VERSION 5.7 ;
  NOWIREEXTENSIONATPIN ON ;
  DIVIDERCHAR "/" ;
  BUSBITCHARS "[]" ;
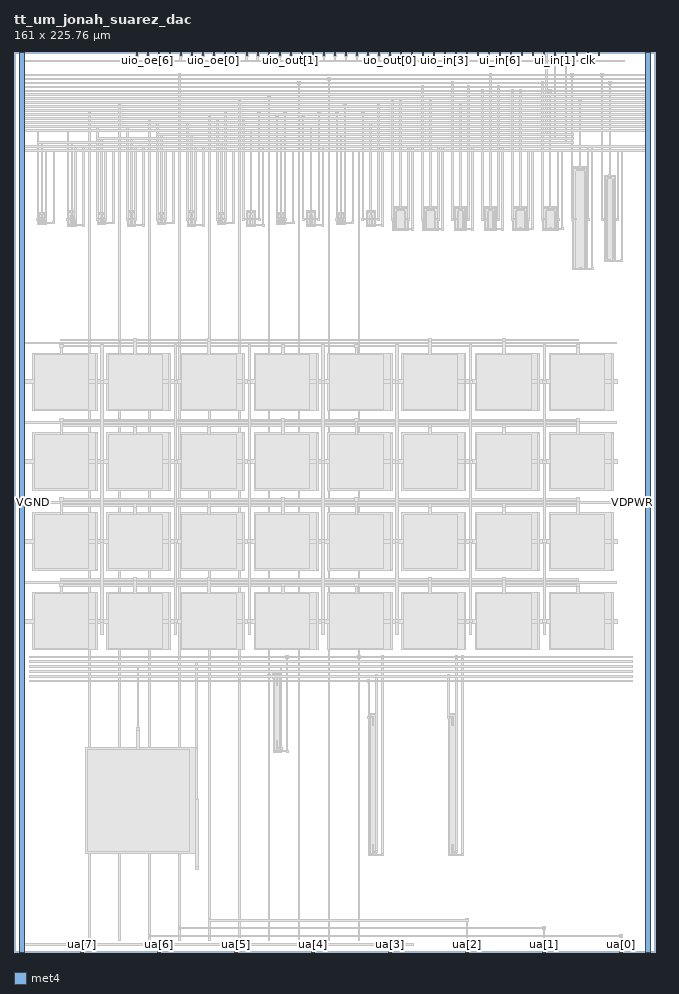
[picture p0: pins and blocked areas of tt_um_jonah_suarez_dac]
MACRO tt_um_jonah_suarez_dac
  CLASS BLOCK ;
  FOREIGN tt_um_jonah_suarez_dac ;
  ORIGIN 0.000 0.000 ;
  SIZE 161.000 BY 225.760 ;
  PIN clk
    DIRECTION INPUT ;
    USE SIGNAL ;
    PORT
      LAYER met4 ;
        RECT 143.830 224.760 144.130 225.760 ;
    END
  END clk
  PIN ena
    DIRECTION INPUT ;
    USE SIGNAL ;
    PORT
      LAYER met4 ;
        RECT 146.590 224.760 146.890 225.760 ;
    END
  END ena
  PIN rst_n
    DIRECTION INPUT ;
    USE SIGNAL ;
    PORT
      LAYER met4 ;
        RECT 141.070 224.760 141.370 225.760 ;
    END
  END rst_n
  PIN ua[0]
    DIRECTION INOUT ;
    USE SIGNAL ;
    ANTENNADIFFAREA 0.870000 ;
    PORT
      LAYER met4 ;
        RECT 151.810 0.000 152.710 1.000 ;
    END
  END ua[0]
  PIN ua[1]
    DIRECTION INOUT ;
    USE SIGNAL ;
    ANTENNAGATEAREA 4.000000 ;
    ANTENNADIFFAREA 12.759999 ;
    PORT
      LAYER met4 ;
        RECT 132.490 0.000 133.390 1.000 ;
    END
  END ua[1]
  PIN ua[2]
    DIRECTION INOUT ;
    USE SIGNAL ;
    ANTENNADIFFAREA 0.870000 ;
    PORT
      LAYER met4 ;
        RECT 113.170 0.000 114.070 1.000 ;
    END
  END ua[2]
  PIN ua[3]
    DIRECTION INOUT ;
    USE SIGNAL ;
    PORT
      LAYER met4 ;
        RECT 93.850 0.000 94.750 1.000 ;
    END
  END ua[3]
  PIN ua[4]
    DIRECTION INOUT ;
    USE SIGNAL ;
    PORT
      LAYER met4 ;
        RECT 74.530 0.000 75.430 1.000 ;
    END
  END ua[4]
  PIN ua[5]
    DIRECTION INOUT ;
    USE SIGNAL ;
    PORT
      LAYER met4 ;
        RECT 55.210 0.000 56.110 1.000 ;
    END
  END ua[5]
  PIN ua[6]
    DIRECTION INOUT ;
    USE SIGNAL ;
    PORT
      LAYER met4 ;
        RECT 35.890 0.000 36.790 1.000 ;
    END
  END ua[6]
  PIN ua[7]
    DIRECTION INOUT ;
    USE SIGNAL ;
    PORT
      LAYER met4 ;
        RECT 16.570 0.000 17.470 1.000 ;
    END
  END ua[7]
  PIN ui_in[0]
    DIRECTION INPUT ;
    USE SIGNAL ;
    ANTENNAGATEAREA 0.600000 ;
    PORT
      LAYER met4 ;
        RECT 138.310 224.760 138.610 225.760 ;
    END
  END ui_in[0]
  PIN ui_in[1]
    DIRECTION INPUT ;
    USE SIGNAL ;
    ANTENNAGATEAREA 0.600000 ;
    PORT
      LAYER met4 ;
        RECT 135.550 224.760 135.850 225.760 ;
    END
  END ui_in[1]
  PIN ui_in[2]
    DIRECTION INPUT ;
    USE SIGNAL ;
    ANTENNAGATEAREA 0.600000 ;
    PORT
      LAYER met4 ;
        RECT 132.790 224.760 133.090 225.760 ;
    END
  END ui_in[2]
  PIN ui_in[3]
    DIRECTION INPUT ;
    USE SIGNAL ;
    PORT
      LAYER met4 ;
        RECT 130.030 224.760 130.330 225.760 ;
    END
  END ui_in[3]
  PIN ui_in[4]
    DIRECTION INPUT ;
    USE SIGNAL ;
    PORT
      LAYER met4 ;
        RECT 127.270 224.760 127.570 225.760 ;
    END
  END ui_in[4]
  PIN ui_in[5]
    DIRECTION INPUT ;
    USE SIGNAL ;
    PORT
      LAYER met4 ;
        RECT 124.510 224.760 124.810 225.760 ;
    END
  END ui_in[5]
  PIN ui_in[6]
    DIRECTION INPUT ;
    USE SIGNAL ;
    PORT
      LAYER met4 ;
        RECT 121.750 224.760 122.050 225.760 ;
    END
  END ui_in[6]
  PIN ui_in[7]
    DIRECTION INPUT ;
    USE SIGNAL ;
    PORT
      LAYER met4 ;
        RECT 118.990 224.760 119.290 225.760 ;
    END
  END ui_in[7]
  PIN uio_in[0]
    DIRECTION INPUT ;
    USE SIGNAL ;
    PORT
      LAYER met4 ;
        RECT 116.230 224.760 116.530 225.760 ;
    END
  END uio_in[0]
  PIN uio_in[1]
    DIRECTION INPUT ;
    USE SIGNAL ;
    PORT
      LAYER met4 ;
        RECT 113.470 224.760 113.770 225.760 ;
    END
  END uio_in[1]
  PIN uio_in[2]
    DIRECTION INPUT ;
    USE SIGNAL ;
    PORT
      LAYER met4 ;
        RECT 110.710 224.760 111.010 225.760 ;
    END
  END uio_in[2]
  PIN uio_in[3]
    DIRECTION INPUT ;
    USE SIGNAL ;
    PORT
      LAYER met4 ;
        RECT 107.950 224.760 108.250 225.760 ;
    END
  END uio_in[3]
  PIN uio_in[4]
    DIRECTION INPUT ;
    USE SIGNAL ;
    PORT
      LAYER met4 ;
        RECT 105.190 224.760 105.490 225.760 ;
    END
  END uio_in[4]
  PIN uio_in[5]
    DIRECTION INPUT ;
    USE SIGNAL ;
    PORT
      LAYER met4 ;
        RECT 102.430 224.760 102.730 225.760 ;
    END
  END uio_in[5]
  PIN uio_in[6]
    DIRECTION INPUT ;
    USE SIGNAL ;
    PORT
      LAYER met4 ;
        RECT 99.670 224.760 99.970 225.760 ;
    END
  END uio_in[6]
  PIN uio_in[7]
    DIRECTION INPUT ;
    USE SIGNAL ;
    PORT
      LAYER met4 ;
        RECT 96.910 224.760 97.210 225.760 ;
    END
  END uio_in[7]
  PIN uio_oe[0]
    DIRECTION OUTPUT ;
    USE SIGNAL ;
    ANTENNADIFFAREA 62.852798 ;
    PORT
      LAYER met4 ;
        RECT 49.990 224.760 50.290 225.760 ;
    END
  END uio_oe[0]
  PIN uio_oe[1]
    DIRECTION OUTPUT ;
    USE SIGNAL ;
    ANTENNADIFFAREA 62.852798 ;
    PORT
      LAYER met4 ;
        RECT 47.230 224.760 47.530 225.760 ;
    END
  END uio_oe[1]
  PIN uio_oe[2]
    DIRECTION OUTPUT ;
    USE SIGNAL ;
    ANTENNADIFFAREA 62.852798 ;
    PORT
      LAYER met4 ;
        RECT 44.470 224.760 44.770 225.760 ;
    END
  END uio_oe[2]
  PIN uio_oe[3]
    DIRECTION OUTPUT ;
    USE SIGNAL ;
    ANTENNADIFFAREA 62.852798 ;
    PORT
      LAYER met4 ;
        RECT 41.710 224.760 42.010 225.760 ;
    END
  END uio_oe[3]
  PIN uio_oe[4]
    DIRECTION OUTPUT ;
    USE SIGNAL ;
    ANTENNADIFFAREA 62.852798 ;
    PORT
      LAYER met4 ;
        RECT 38.950 224.760 39.250 225.760 ;
    END
  END uio_oe[4]
  PIN uio_oe[5]
    DIRECTION OUTPUT ;
    USE SIGNAL ;
    ANTENNADIFFAREA 62.852798 ;
    PORT
      LAYER met4 ;
        RECT 36.190 224.760 36.490 225.760 ;
    END
  END uio_oe[5]
  PIN uio_oe[6]
    DIRECTION OUTPUT ;
    USE SIGNAL ;
    ANTENNADIFFAREA 62.852798 ;
    PORT
      LAYER met4 ;
        RECT 33.430 224.760 33.730 225.760 ;
    END
  END uio_oe[6]
  PIN uio_oe[7]
    DIRECTION OUTPUT ;
    USE SIGNAL ;
    ANTENNADIFFAREA 62.852798 ;
    PORT
      LAYER met4 ;
        RECT 30.670 224.760 30.970 225.760 ;
    END
  END uio_oe[7]
  PIN uio_out[0]
    DIRECTION OUTPUT ;
    USE SIGNAL ;
    ANTENNADIFFAREA 62.852798 ;
    PORT
      LAYER met4 ;
        RECT 72.070 224.760 72.370 225.760 ;
    END
  END uio_out[0]
  PIN uio_out[1]
    DIRECTION OUTPUT ;
    USE SIGNAL ;
    ANTENNADIFFAREA 62.852798 ;
    PORT
      LAYER met4 ;
        RECT 69.310 224.760 69.610 225.760 ;
    END
  END uio_out[1]
  PIN uio_out[2]
    DIRECTION OUTPUT ;
    USE SIGNAL ;
    ANTENNADIFFAREA 62.852798 ;
    PORT
      LAYER met4 ;
        RECT 66.550 224.760 66.850 225.760 ;
    END
  END uio_out[2]
  PIN uio_out[3]
    DIRECTION OUTPUT ;
    USE SIGNAL ;
    ANTENNADIFFAREA 62.852798 ;
    PORT
      LAYER met4 ;
        RECT 63.790 224.760 64.090 225.760 ;
    END
  END uio_out[3]
  PIN uio_out[4]
    DIRECTION OUTPUT ;
    USE SIGNAL ;
    ANTENNADIFFAREA 62.852798 ;
    PORT
      LAYER met4 ;
        RECT 61.030 224.760 61.330 225.760 ;
    END
  END uio_out[4]
  PIN uio_out[5]
    DIRECTION OUTPUT ;
    USE SIGNAL ;
    ANTENNADIFFAREA 62.852798 ;
    PORT
      LAYER met4 ;
        RECT 58.270 224.760 58.570 225.760 ;
    END
  END uio_out[5]
  PIN uio_out[6]
    DIRECTION OUTPUT ;
    USE SIGNAL ;
    ANTENNADIFFAREA 62.852798 ;
    PORT
      LAYER met4 ;
        RECT 55.510 224.760 55.810 225.760 ;
    END
  END uio_out[6]
  PIN uio_out[7]
    DIRECTION OUTPUT ;
    USE SIGNAL ;
    ANTENNADIFFAREA 62.852798 ;
    PORT
      LAYER met4 ;
        RECT 52.750 224.760 53.050 225.760 ;
    END
  END uio_out[7]
  PIN uo_out[0]
    DIRECTION OUTPUT ;
    USE SIGNAL ;
    ANTENNADIFFAREA 62.852798 ;
    PORT
      LAYER met4 ;
        RECT 94.150 224.760 94.450 225.760 ;
    END
  END uo_out[0]
  PIN uo_out[1]
    DIRECTION OUTPUT ;
    USE SIGNAL ;
    ANTENNADIFFAREA 62.852798 ;
    PORT
      LAYER met4 ;
        RECT 91.390 224.760 91.690 225.760 ;
    END
  END uo_out[1]
  PIN uo_out[2]
    DIRECTION OUTPUT ;
    USE SIGNAL ;
    ANTENNADIFFAREA 62.852798 ;
    PORT
      LAYER met4 ;
        RECT 88.630 224.760 88.930 225.760 ;
    END
  END uo_out[2]
  PIN uo_out[3]
    DIRECTION OUTPUT ;
    USE SIGNAL ;
    ANTENNADIFFAREA 62.852798 ;
    PORT
      LAYER met4 ;
        RECT 85.870 224.760 86.170 225.760 ;
    END
  END uo_out[3]
  PIN uo_out[4]
    DIRECTION OUTPUT ;
    USE SIGNAL ;
    ANTENNADIFFAREA 62.852798 ;
    PORT
      LAYER met4 ;
        RECT 83.110 224.760 83.410 225.760 ;
    END
  END uo_out[4]
  PIN uo_out[5]
    DIRECTION OUTPUT ;
    USE SIGNAL ;
    ANTENNADIFFAREA 62.852798 ;
    PORT
      LAYER met4 ;
        RECT 80.350 224.760 80.650 225.760 ;
    END
  END uo_out[5]
  PIN uo_out[6]
    DIRECTION OUTPUT ;
    USE SIGNAL ;
    ANTENNADIFFAREA 62.852798 ;
    PORT
      LAYER met4 ;
        RECT 77.590 224.760 77.890 225.760 ;
    END
  END uo_out[6]
  PIN uo_out[7]
    DIRECTION OUTPUT ;
    USE SIGNAL ;
    ANTENNADIFFAREA 62.852798 ;
    PORT
      LAYER met4 ;
        RECT 74.830 224.760 75.130 225.760 ;
    END
  END uo_out[7]
  PIN VGND
    DIRECTION INPUT ;
    USE GROUND ;
    PORT
      LAYER met4 ;
        RECT 1.400 0.000 2.600 225.760 ;
    END
  END VGND
  PIN VDPWR
    DIRECTION INPUT ;
    USE POWER ;
    PORT
      LAYER met4 ;
        RECT 158.400 0.000 159.600 225.760 ;
    END
  END VDPWR
  OBS
      LAYER pwell ;
        RECT 5.945 182.605 8.055 185.395 ;
      LAYER nwell ;
        RECT 13.445 182.080 15.555 185.920 ;
      LAYER pwell ;
        RECT 20.945 182.605 23.055 185.395 ;
      LAYER nwell ;
        RECT 28.445 182.080 30.555 185.920 ;
      LAYER pwell ;
        RECT 35.945 182.605 38.055 185.395 ;
      LAYER nwell ;
        RECT 43.445 182.080 45.555 185.920 ;
      LAYER pwell ;
        RECT 50.945 182.605 53.055 185.395 ;
      LAYER nwell ;
        RECT 58.345 182.080 60.655 185.920 ;
      LAYER pwell ;
        RECT 65.945 182.605 68.055 185.395 ;
      LAYER nwell ;
        RECT 73.345 182.080 75.655 185.920 ;
      LAYER pwell ;
        RECT 80.945 182.605 83.055 185.395 ;
      LAYER nwell ;
        RECT 88.345 182.080 90.655 185.920 ;
        RECT 95.020 181.080 98.980 186.920 ;
        RECT 102.520 181.080 106.480 186.920 ;
        RECT 110.520 181.080 113.480 186.920 ;
        RECT 118.020 181.080 120.980 186.920 ;
      LAYER pwell ;
        RECT 125.020 181.105 128.980 186.895 ;
        RECT 132.520 181.105 136.480 186.895 ;
      LAYER nwell ;
        RECT 140.020 171.080 143.980 196.920 ;
      LAYER pwell ;
        RECT 148.020 173.105 150.980 194.895 ;
        RECT 64.995 50.090 67.005 69.910 ;
        RECT 88.995 24.090 91.005 59.910 ;
        RECT 108.995 24.090 111.005 59.910 ;
      LAYER li1 ;
        RECT 140.200 196.570 143.800 196.740 ;
        RECT 95.200 186.570 98.800 186.740 ;
        RECT 13.625 185.570 15.375 185.740 ;
        RECT 6.125 185.045 7.875 185.215 ;
        RECT 6.125 182.955 6.295 185.045 ;
        RECT 6.835 184.535 7.165 184.705 ;
        RECT 6.695 183.325 6.865 184.365 ;
        RECT 7.135 183.325 7.305 184.365 ;
        RECT 7.705 182.955 7.875 185.045 ;
        RECT 6.125 182.785 7.875 182.955 ;
        RECT 13.625 182.430 13.795 185.570 ;
        RECT 14.335 185.055 14.665 185.225 ;
        RECT 14.195 182.800 14.365 184.840 ;
        RECT 14.635 182.800 14.805 184.840 ;
        RECT 15.205 182.430 15.375 185.570 ;
        RECT 28.625 185.570 30.375 185.740 ;
        RECT 21.125 185.045 22.875 185.215 ;
        RECT 21.125 182.955 21.295 185.045 ;
        RECT 21.835 184.535 22.165 184.705 ;
        RECT 21.695 183.325 21.865 184.365 ;
        RECT 22.135 183.325 22.305 184.365 ;
        RECT 22.705 182.955 22.875 185.045 ;
        RECT 21.125 182.785 22.875 182.955 ;
        RECT 13.625 182.260 15.375 182.430 ;
        RECT 28.625 182.430 28.795 185.570 ;
        RECT 29.335 185.055 29.665 185.225 ;
        RECT 29.195 182.800 29.365 184.840 ;
        RECT 29.635 182.800 29.805 184.840 ;
        RECT 30.205 182.430 30.375 185.570 ;
        RECT 43.625 185.570 45.375 185.740 ;
        RECT 36.125 185.045 37.875 185.215 ;
        RECT 36.125 182.955 36.295 185.045 ;
        RECT 36.835 184.535 37.165 184.705 ;
        RECT 36.695 183.325 36.865 184.365 ;
        RECT 37.135 183.325 37.305 184.365 ;
        RECT 37.705 182.955 37.875 185.045 ;
        RECT 36.125 182.785 37.875 182.955 ;
        RECT 28.625 182.260 30.375 182.430 ;
        RECT 43.625 182.430 43.795 185.570 ;
        RECT 44.335 185.055 44.665 185.225 ;
        RECT 44.195 182.800 44.365 184.840 ;
        RECT 44.635 182.800 44.805 184.840 ;
        RECT 45.205 182.430 45.375 185.570 ;
        RECT 58.525 185.570 60.475 185.740 ;
        RECT 51.125 185.045 52.875 185.215 ;
        RECT 51.125 182.955 51.295 185.045 ;
        RECT 51.835 184.535 52.165 184.705 ;
        RECT 51.695 183.325 51.865 184.365 ;
        RECT 52.135 183.325 52.305 184.365 ;
        RECT 52.705 182.955 52.875 185.045 ;
        RECT 51.125 182.785 52.875 182.955 ;
        RECT 43.625 182.260 45.375 182.430 ;
        RECT 58.525 182.430 58.695 185.570 ;
        RECT 59.325 185.055 59.675 185.225 ;
        RECT 59.095 182.800 59.265 184.840 ;
        RECT 59.735 182.800 59.905 184.840 ;
        RECT 60.305 182.430 60.475 185.570 ;
        RECT 73.525 185.570 75.475 185.740 ;
        RECT 66.125 185.045 67.875 185.215 ;
        RECT 66.125 182.955 66.295 185.045 ;
        RECT 66.835 184.535 67.165 184.705 ;
        RECT 66.695 183.325 66.865 184.365 ;
        RECT 67.135 183.325 67.305 184.365 ;
        RECT 67.705 182.955 67.875 185.045 ;
        RECT 66.125 182.785 67.875 182.955 ;
        RECT 58.525 182.260 60.475 182.430 ;
        RECT 73.525 182.430 73.695 185.570 ;
        RECT 74.325 185.055 74.675 185.225 ;
        RECT 74.095 182.800 74.265 184.840 ;
        RECT 74.735 182.800 74.905 184.840 ;
        RECT 75.305 182.430 75.475 185.570 ;
        RECT 88.525 185.570 90.475 185.740 ;
        RECT 81.125 185.045 82.875 185.215 ;
        RECT 81.125 182.955 81.295 185.045 ;
        RECT 81.835 184.535 82.165 184.705 ;
        RECT 81.695 183.325 81.865 184.365 ;
        RECT 82.135 183.325 82.305 184.365 ;
        RECT 82.705 182.955 82.875 185.045 ;
        RECT 81.125 182.785 82.875 182.955 ;
        RECT 73.525 182.260 75.475 182.430 ;
        RECT 88.525 182.430 88.695 185.570 ;
        RECT 89.325 185.055 89.675 185.225 ;
        RECT 89.095 182.800 89.265 184.840 ;
        RECT 89.735 182.800 89.905 184.840 ;
        RECT 90.305 182.430 90.475 185.570 ;
        RECT 88.525 182.260 90.475 182.430 ;
        RECT 95.200 181.430 95.370 186.570 ;
        RECT 96.000 186.055 98.000 186.225 ;
        RECT 95.770 181.800 95.940 185.840 ;
        RECT 98.060 181.800 98.230 185.840 ;
        RECT 98.630 181.430 98.800 186.570 ;
        RECT 95.200 181.260 98.800 181.430 ;
        RECT 102.700 186.570 106.300 186.740 ;
        RECT 102.700 181.430 102.870 186.570 ;
        RECT 103.500 186.055 105.500 186.225 ;
        RECT 103.270 181.800 103.440 185.840 ;
        RECT 105.560 181.800 105.730 185.840 ;
        RECT 106.130 181.430 106.300 186.570 ;
        RECT 102.700 181.260 106.300 181.430 ;
        RECT 110.700 186.570 113.300 186.740 ;
        RECT 110.700 181.430 110.870 186.570 ;
        RECT 111.500 186.055 112.500 186.225 ;
        RECT 111.270 181.800 111.440 185.840 ;
        RECT 112.560 181.800 112.730 185.840 ;
        RECT 113.130 181.430 113.300 186.570 ;
        RECT 110.700 181.260 113.300 181.430 ;
        RECT 118.200 186.570 120.800 186.740 ;
        RECT 118.200 181.430 118.370 186.570 ;
        RECT 119.000 186.055 120.000 186.225 ;
        RECT 118.770 181.800 118.940 185.840 ;
        RECT 120.060 181.800 120.230 185.840 ;
        RECT 120.630 181.430 120.800 186.570 ;
        RECT 118.200 181.260 120.800 181.430 ;
        RECT 125.200 186.545 128.800 186.715 ;
        RECT 125.200 181.455 125.370 186.545 ;
        RECT 126.000 186.035 128.000 186.205 ;
        RECT 125.770 181.825 125.940 185.865 ;
        RECT 128.060 181.825 128.230 185.865 ;
        RECT 128.630 181.455 128.800 186.545 ;
        RECT 125.200 181.285 128.800 181.455 ;
        RECT 132.700 186.545 136.300 186.715 ;
        RECT 132.700 181.455 132.870 186.545 ;
        RECT 133.500 186.035 135.500 186.205 ;
        RECT 133.270 181.825 133.440 185.865 ;
        RECT 135.560 181.825 135.730 185.865 ;
        RECT 136.130 181.455 136.300 186.545 ;
        RECT 132.700 181.285 136.300 181.455 ;
        RECT 140.200 171.430 140.370 196.570 ;
        RECT 141.000 196.055 143.000 196.225 ;
        RECT 140.770 171.800 140.940 195.840 ;
        RECT 143.060 171.800 143.230 195.840 ;
        RECT 143.630 171.430 143.800 196.570 ;
        RECT 148.200 194.545 150.800 194.715 ;
        RECT 148.200 173.455 148.370 194.545 ;
        RECT 149.000 194.035 150.000 194.205 ;
        RECT 148.770 173.825 148.940 193.865 ;
        RECT 150.060 173.825 150.230 193.865 ;
        RECT 150.630 173.455 150.800 194.545 ;
        RECT 148.200 173.285 150.800 173.455 ;
        RECT 140.200 171.260 143.800 171.430 ;
        RECT 65.175 69.560 66.825 69.730 ;
        RECT 65.175 50.440 65.345 69.560 ;
        RECT 65.825 66.920 66.175 69.080 ;
        RECT 65.825 50.920 66.175 53.080 ;
        RECT 66.655 50.440 66.825 69.560 ;
        RECT 65.175 50.270 66.825 50.440 ;
        RECT 89.175 59.560 90.825 59.730 ;
        RECT 89.175 24.440 89.345 59.560 ;
        RECT 89.825 56.920 90.175 59.080 ;
        RECT 89.825 24.920 90.175 27.080 ;
        RECT 90.655 24.440 90.825 59.560 ;
        RECT 89.175 24.270 90.825 24.440 ;
        RECT 109.175 59.560 110.825 59.730 ;
        RECT 109.175 24.440 109.345 59.560 ;
        RECT 109.825 56.920 110.175 59.080 ;
        RECT 109.825 24.920 110.175 27.080 ;
        RECT 110.655 24.440 110.825 59.560 ;
        RECT 109.175 24.270 110.825 24.440 ;
      LAYER met1 ;
        RECT 41.250 219.750 41.750 220.250 ;
        RECT 26.250 212.750 26.750 213.250 ;
        RECT 18.750 210.750 19.250 211.250 ;
        RECT 14.250 185.490 14.750 185.990 ;
        RECT 6.750 184.970 7.250 185.470 ;
        RECT 14.370 185.255 14.630 185.490 ;
        RECT 14.355 185.025 14.645 185.255 ;
        RECT 14.370 185.010 14.630 185.025 ;
        RECT 6.870 184.735 7.130 184.970 ;
        RECT 6.855 184.505 7.145 184.735 ;
        RECT 6.870 184.490 7.130 184.505 ;
        RECT 5.750 183.985 6.250 184.095 ;
        RECT 6.665 183.985 6.895 184.345 ;
        RECT 7.105 183.985 7.335 184.345 ;
        RECT 7.750 183.985 8.250 184.095 ;
        RECT 5.750 183.705 6.920 183.985 ;
        RECT 7.080 183.705 8.250 183.985 ;
        RECT 5.750 183.595 6.250 183.705 ;
        RECT 6.665 183.345 6.895 183.705 ;
        RECT 7.105 183.345 7.335 183.705 ;
        RECT 7.750 183.595 8.250 183.705 ;
        RECT 13.250 183.960 13.750 184.070 ;
        RECT 14.165 183.960 14.395 184.820 ;
        RECT 14.605 183.960 14.835 184.820 ;
        RECT 15.250 183.960 15.750 184.070 ;
        RECT 13.250 183.680 14.420 183.960 ;
        RECT 14.580 183.680 15.750 183.960 ;
        RECT 13.250 183.570 13.750 183.680 ;
        RECT 6.750 183.010 7.250 183.120 ;
        RECT 9.750 183.010 10.250 183.120 ;
        RECT 6.750 182.730 10.250 183.010 ;
        RECT 14.165 182.820 14.395 183.680 ;
        RECT 14.605 182.820 14.835 183.680 ;
        RECT 15.250 183.570 15.750 183.680 ;
        RECT 6.750 182.620 7.250 182.730 ;
        RECT 9.750 182.620 10.250 182.730 ;
        RECT 14.250 182.485 14.750 182.595 ;
        RECT 17.250 182.485 17.750 182.595 ;
        RECT 14.250 182.205 17.750 182.485 ;
        RECT 14.250 182.095 14.750 182.205 ;
        RECT 17.250 182.095 17.750 182.205 ;
        RECT 18.800 152.250 19.200 210.750 ;
        RECT 21.750 184.970 22.250 185.470 ;
        RECT 21.870 184.735 22.130 184.970 ;
        RECT 21.855 184.505 22.145 184.735 ;
        RECT 21.870 184.490 22.130 184.505 ;
        RECT 20.750 183.985 21.250 184.095 ;
        RECT 21.665 183.985 21.895 184.345 ;
        RECT 22.105 183.985 22.335 184.345 ;
        RECT 22.750 183.985 23.250 184.095 ;
        RECT 20.750 183.705 21.920 183.985 ;
        RECT 22.080 183.705 23.250 183.985 ;
        RECT 20.750 183.595 21.250 183.705 ;
        RECT 21.665 183.345 21.895 183.705 ;
        RECT 22.105 183.345 22.335 183.705 ;
        RECT 22.750 183.595 23.250 183.705 ;
        RECT 21.750 183.010 22.250 183.120 ;
        RECT 24.750 183.010 25.250 183.120 ;
        RECT 21.750 182.730 25.250 183.010 ;
        RECT 21.750 182.620 22.250 182.730 ;
        RECT 24.750 182.620 25.250 182.730 ;
        RECT 26.300 153.750 26.700 212.750 ;
        RECT 33.750 208.750 34.250 209.250 ;
        RECT 29.250 185.490 29.750 185.990 ;
        RECT 29.370 185.255 29.630 185.490 ;
        RECT 29.355 185.025 29.645 185.255 ;
        RECT 29.370 185.010 29.630 185.025 ;
        RECT 28.250 183.960 28.750 184.070 ;
        RECT 29.165 183.960 29.395 184.820 ;
        RECT 29.605 183.960 29.835 184.820 ;
        RECT 30.250 183.960 30.750 184.070 ;
        RECT 28.250 183.680 29.420 183.960 ;
        RECT 29.580 183.680 30.750 183.960 ;
        RECT 28.250 183.570 28.750 183.680 ;
        RECT 29.165 182.820 29.395 183.680 ;
        RECT 29.605 182.820 29.835 183.680 ;
        RECT 30.250 183.570 30.750 183.680 ;
        RECT 29.250 182.485 29.750 182.595 ;
        RECT 32.250 182.485 32.750 182.595 ;
        RECT 29.250 182.205 32.750 182.485 ;
        RECT 29.250 182.095 29.750 182.205 ;
        RECT 32.250 182.095 32.750 182.205 ;
        RECT 26.250 153.250 26.750 153.750 ;
        RECT 18.750 151.750 19.250 152.250 ;
        RECT 18.800 132.250 19.200 151.750 ;
        RECT 26.300 133.750 26.700 153.250 ;
        RECT 26.250 133.250 26.750 133.750 ;
        RECT 18.750 131.750 19.250 132.250 ;
        RECT 18.800 112.250 19.200 131.750 ;
        RECT 26.300 113.750 26.700 133.250 ;
        RECT 26.250 113.250 26.750 113.750 ;
        RECT 18.750 111.750 19.250 112.250 ;
        RECT 18.800 92.250 19.200 111.750 ;
        RECT 26.300 93.750 26.700 113.250 ;
        RECT 26.250 93.250 26.750 93.750 ;
        RECT 18.750 91.750 19.250 92.250 ;
        RECT 18.800 2.800 19.200 91.750 ;
        RECT 26.300 2.800 26.700 93.250 ;
        RECT 33.800 4.250 34.200 208.750 ;
        RECT 36.750 184.970 37.250 185.470 ;
        RECT 36.870 184.735 37.130 184.970 ;
        RECT 36.855 184.505 37.145 184.735 ;
        RECT 36.870 184.490 37.130 184.505 ;
        RECT 35.750 183.985 36.250 184.095 ;
        RECT 36.665 183.985 36.895 184.345 ;
        RECT 37.105 183.985 37.335 184.345 ;
        RECT 37.750 183.985 38.250 184.095 ;
        RECT 35.750 183.705 36.920 183.985 ;
        RECT 37.080 183.705 38.250 183.985 ;
        RECT 35.750 183.595 36.250 183.705 ;
        RECT 36.665 183.345 36.895 183.705 ;
        RECT 37.105 183.345 37.335 183.705 ;
        RECT 37.750 183.595 38.250 183.705 ;
        RECT 36.750 183.010 37.250 183.120 ;
        RECT 39.750 183.010 40.250 183.120 ;
        RECT 36.750 182.730 40.250 183.010 ;
        RECT 36.750 182.620 37.250 182.730 ;
        RECT 39.750 182.620 40.250 182.730 ;
        RECT 41.300 73.050 41.700 219.750 ;
        RECT 78.750 218.750 79.250 219.250 ;
        RECT 71.250 217.750 71.750 218.250 ;
        RECT 63.750 214.750 64.250 215.250 ;
        RECT 56.250 213.750 56.750 214.250 ;
        RECT 48.750 209.750 49.250 210.250 ;
        RECT 44.250 185.490 44.750 185.990 ;
        RECT 44.370 185.255 44.630 185.490 ;
        RECT 44.355 185.025 44.645 185.255 ;
        RECT 44.370 185.010 44.630 185.025 ;
        RECT 43.250 183.960 43.750 184.070 ;
        RECT 44.165 183.960 44.395 184.820 ;
        RECT 44.605 183.960 44.835 184.820 ;
        RECT 45.250 183.960 45.750 184.070 ;
        RECT 43.250 183.680 44.420 183.960 ;
        RECT 44.580 183.680 45.750 183.960 ;
        RECT 43.250 183.570 43.750 183.680 ;
        RECT 44.165 182.820 44.395 183.680 ;
        RECT 44.605 182.820 44.835 183.680 ;
        RECT 45.250 183.570 45.750 183.680 ;
        RECT 44.250 182.485 44.750 182.595 ;
        RECT 47.250 182.485 47.750 182.595 ;
        RECT 44.250 182.205 47.750 182.485 ;
        RECT 44.250 182.095 44.750 182.205 ;
        RECT 47.250 182.095 47.750 182.205 ;
        RECT 41.250 72.550 41.750 73.050 ;
        RECT 41.300 6.250 41.700 72.550 ;
        RECT 48.800 8.250 49.200 209.750 ;
        RECT 51.750 184.970 52.250 185.470 ;
        RECT 51.870 184.735 52.130 184.970 ;
        RECT 51.855 184.505 52.145 184.735 ;
        RECT 51.870 184.490 52.130 184.505 ;
        RECT 50.750 183.985 51.250 184.095 ;
        RECT 51.665 183.985 51.895 184.345 ;
        RECT 52.105 183.985 52.335 184.345 ;
        RECT 52.750 183.985 53.250 184.095 ;
        RECT 50.750 183.705 51.920 183.985 ;
        RECT 52.080 183.705 53.250 183.985 ;
        RECT 50.750 183.595 51.250 183.705 ;
        RECT 51.665 183.345 51.895 183.705 ;
        RECT 52.105 183.345 52.335 183.705 ;
        RECT 52.750 183.595 53.250 183.705 ;
        RECT 51.750 183.010 52.250 183.120 ;
        RECT 54.750 183.010 55.250 183.120 ;
        RECT 51.750 182.730 55.250 183.010 ;
        RECT 51.750 182.620 52.250 182.730 ;
        RECT 54.750 182.620 55.250 182.730 ;
        RECT 56.300 68.250 56.700 213.750 ;
        RECT 59.250 185.490 59.750 185.990 ;
        RECT 59.370 185.255 59.630 185.490 ;
        RECT 59.345 185.025 59.655 185.255 ;
        RECT 59.370 185.010 59.630 185.025 ;
        RECT 57.250 183.960 57.750 184.070 ;
        RECT 59.065 183.960 59.295 184.820 ;
        RECT 59.705 183.960 59.935 184.820 ;
        RECT 61.250 183.960 61.750 184.070 ;
        RECT 57.250 183.680 59.320 183.960 ;
        RECT 59.680 183.680 61.750 183.960 ;
        RECT 57.250 183.570 57.750 183.680 ;
        RECT 59.065 182.820 59.295 183.680 ;
        RECT 59.705 182.820 59.935 183.680 ;
        RECT 61.250 183.570 61.750 183.680 ;
        RECT 59.250 182.485 59.750 182.595 ;
        RECT 62.250 182.485 62.750 182.595 ;
        RECT 59.250 182.205 62.750 182.485 ;
        RECT 59.250 182.095 59.750 182.205 ;
        RECT 62.250 182.095 62.750 182.205 ;
        RECT 63.800 69.450 64.200 214.750 ;
        RECT 66.750 184.970 67.250 185.470 ;
        RECT 66.870 184.735 67.130 184.970 ;
        RECT 66.855 184.505 67.145 184.735 ;
        RECT 66.870 184.490 67.130 184.505 ;
        RECT 65.750 183.985 66.250 184.095 ;
        RECT 66.665 183.985 66.895 184.345 ;
        RECT 67.105 183.985 67.335 184.345 ;
        RECT 67.750 183.985 68.250 184.095 ;
        RECT 65.750 183.705 66.920 183.985 ;
        RECT 67.080 183.705 68.250 183.985 ;
        RECT 65.750 183.595 66.250 183.705 ;
        RECT 66.665 183.345 66.895 183.705 ;
        RECT 67.105 183.345 67.335 183.705 ;
        RECT 67.750 183.595 68.250 183.705 ;
        RECT 66.750 183.010 67.250 183.120 ;
        RECT 69.750 183.010 70.250 183.120 ;
        RECT 66.750 182.730 70.250 183.010 ;
        RECT 66.750 182.620 67.250 182.730 ;
        RECT 69.750 182.620 70.250 182.730 ;
        RECT 71.300 70.650 71.700 217.750 ;
        RECT 74.250 185.490 74.750 185.990 ;
        RECT 74.370 185.255 74.630 185.490 ;
        RECT 74.345 185.025 74.655 185.255 ;
        RECT 74.370 185.010 74.630 185.025 ;
        RECT 72.250 183.960 72.750 184.070 ;
        RECT 74.065 183.960 74.295 184.820 ;
        RECT 74.705 183.960 74.935 184.820 ;
        RECT 76.250 183.960 76.750 184.070 ;
        RECT 72.250 183.680 74.320 183.960 ;
        RECT 74.680 183.680 76.750 183.960 ;
        RECT 72.250 183.570 72.750 183.680 ;
        RECT 74.065 182.820 74.295 183.680 ;
        RECT 74.705 182.820 74.935 183.680 ;
        RECT 76.250 183.570 76.750 183.680 ;
        RECT 74.250 182.485 74.750 182.595 ;
        RECT 77.250 182.485 77.750 182.595 ;
        RECT 74.250 182.205 77.750 182.485 ;
        RECT 74.250 182.095 74.750 182.205 ;
        RECT 77.250 182.095 77.750 182.205 ;
        RECT 78.800 71.850 79.200 218.750 ;
        RECT 86.250 200.750 86.750 201.250 ;
        RECT 81.750 184.970 82.250 185.470 ;
        RECT 81.870 184.735 82.130 184.970 ;
        RECT 81.855 184.505 82.145 184.735 ;
        RECT 81.870 184.490 82.130 184.505 ;
        RECT 80.750 183.985 81.250 184.095 ;
        RECT 81.665 183.985 81.895 184.345 ;
        RECT 82.105 183.985 82.335 184.345 ;
        RECT 82.750 183.985 83.250 184.095 ;
        RECT 80.750 183.705 81.920 183.985 ;
        RECT 82.080 183.705 83.250 183.985 ;
        RECT 80.750 183.595 81.250 183.705 ;
        RECT 81.665 183.345 81.895 183.705 ;
        RECT 82.105 183.345 82.335 183.705 ;
        RECT 82.750 183.595 83.250 183.705 ;
        RECT 81.750 183.010 82.250 183.120 ;
        RECT 84.750 183.010 85.250 183.120 ;
        RECT 81.750 182.730 85.250 183.010 ;
        RECT 81.750 182.620 82.250 182.730 ;
        RECT 84.750 182.620 85.250 182.730 ;
        RECT 86.300 153.000 86.700 200.750 ;
        RECT 141.750 196.490 142.250 196.990 ;
        RECT 141.870 196.255 142.130 196.490 ;
        RECT 141.020 196.025 142.980 196.255 ;
        RECT 141.870 196.010 142.130 196.025 ;
        RECT 96.750 186.490 97.250 186.990 ;
        RECT 104.250 186.490 104.750 186.990 ;
        RECT 111.750 186.490 112.250 186.990 ;
        RECT 119.250 186.490 119.750 186.990 ;
        RECT 96.870 186.255 97.130 186.490 ;
        RECT 104.370 186.255 104.630 186.490 ;
        RECT 111.870 186.255 112.130 186.490 ;
        RECT 119.370 186.255 119.630 186.490 ;
        RECT 126.750 186.470 127.250 186.970 ;
        RECT 134.250 186.470 134.750 186.970 ;
        RECT 96.020 186.025 97.980 186.255 ;
        RECT 103.520 186.025 105.480 186.255 ;
        RECT 111.520 186.025 112.480 186.255 ;
        RECT 119.020 186.025 119.980 186.255 ;
        RECT 126.870 186.235 127.130 186.470 ;
        RECT 134.370 186.235 134.630 186.470 ;
        RECT 96.870 186.010 97.130 186.025 ;
        RECT 104.370 186.010 104.630 186.025 ;
        RECT 111.870 186.010 112.130 186.025 ;
        RECT 119.370 186.010 119.630 186.025 ;
        RECT 126.020 186.005 127.980 186.235 ;
        RECT 133.520 186.005 135.480 186.235 ;
        RECT 126.870 185.990 127.130 186.005 ;
        RECT 134.370 185.990 134.630 186.005 ;
        RECT 89.250 185.490 89.750 185.990 ;
        RECT 89.370 185.255 89.630 185.490 ;
        RECT 89.345 185.025 89.655 185.255 ;
        RECT 89.370 185.010 89.630 185.025 ;
        RECT 87.250 183.960 87.750 184.070 ;
        RECT 89.065 183.960 89.295 184.820 ;
        RECT 89.705 183.960 89.935 184.820 ;
        RECT 91.250 183.960 91.750 184.070 ;
        RECT 87.250 183.680 89.320 183.960 ;
        RECT 89.680 183.680 91.750 183.960 ;
        RECT 87.250 183.570 87.750 183.680 ;
        RECT 89.065 182.820 89.295 183.680 ;
        RECT 89.705 182.820 89.935 183.680 ;
        RECT 91.250 183.570 91.750 183.680 ;
        RECT 94.750 183.960 95.250 184.070 ;
        RECT 95.740 183.960 95.970 185.820 ;
        RECT 98.030 183.960 98.260 185.820 ;
        RECT 98.750 183.960 99.250 184.070 ;
        RECT 94.750 183.680 95.995 183.960 ;
        RECT 98.005 183.680 99.250 183.960 ;
        RECT 94.750 183.570 95.250 183.680 ;
        RECT 89.250 182.485 89.750 182.595 ;
        RECT 92.250 182.485 92.750 182.595 ;
        RECT 89.250 182.205 92.750 182.485 ;
        RECT 89.250 182.095 89.750 182.205 ;
        RECT 92.250 182.095 92.750 182.205 ;
        RECT 95.740 181.820 95.970 183.680 ;
        RECT 98.030 181.820 98.260 183.680 ;
        RECT 98.750 183.570 99.250 183.680 ;
        RECT 102.250 183.960 102.750 184.070 ;
        RECT 103.240 183.960 103.470 185.820 ;
        RECT 105.530 183.960 105.760 185.820 ;
        RECT 106.250 183.960 106.750 184.070 ;
        RECT 102.250 183.680 103.495 183.960 ;
        RECT 105.505 183.680 106.750 183.960 ;
        RECT 102.250 183.570 102.750 183.680 ;
        RECT 103.240 181.820 103.470 183.680 ;
        RECT 105.530 181.820 105.760 183.680 ;
        RECT 106.250 183.570 106.750 183.680 ;
        RECT 109.750 183.960 110.250 184.070 ;
        RECT 111.240 183.960 111.470 185.820 ;
        RECT 112.530 183.960 112.760 185.820 ;
        RECT 113.750 183.960 114.250 184.070 ;
        RECT 109.750 183.680 111.495 183.960 ;
        RECT 112.505 183.680 114.250 183.960 ;
        RECT 109.750 183.570 110.250 183.680 ;
        RECT 111.240 181.820 111.470 183.680 ;
        RECT 112.530 181.820 112.760 183.680 ;
        RECT 113.750 183.570 114.250 183.680 ;
        RECT 117.250 183.960 117.750 184.070 ;
        RECT 118.740 183.960 118.970 185.820 ;
        RECT 120.030 183.960 120.260 185.820 ;
        RECT 121.250 183.960 121.750 184.070 ;
        RECT 117.250 183.680 118.995 183.960 ;
        RECT 120.005 183.680 121.750 183.960 ;
        RECT 117.250 183.570 117.750 183.680 ;
        RECT 118.740 181.820 118.970 183.680 ;
        RECT 120.030 181.820 120.260 183.680 ;
        RECT 121.250 183.570 121.750 183.680 ;
        RECT 124.750 183.985 125.250 184.095 ;
        RECT 125.740 183.985 125.970 185.845 ;
        RECT 128.030 183.985 128.260 185.845 ;
        RECT 128.750 183.985 129.250 184.095 ;
        RECT 124.750 183.705 125.995 183.985 ;
        RECT 128.005 183.705 129.250 183.985 ;
        RECT 124.750 183.595 125.250 183.705 ;
        RECT 125.740 181.845 125.970 183.705 ;
        RECT 128.030 181.845 128.260 183.705 ;
        RECT 128.750 183.595 129.250 183.705 ;
        RECT 132.250 183.985 132.750 184.095 ;
        RECT 133.240 183.985 133.470 185.845 ;
        RECT 135.530 183.985 135.760 185.845 ;
        RECT 136.250 183.985 136.750 184.095 ;
        RECT 132.250 183.705 133.495 183.985 ;
        RECT 135.505 183.705 136.750 183.985 ;
        RECT 132.250 183.595 132.750 183.705 ;
        RECT 133.240 181.845 133.470 183.705 ;
        RECT 135.530 181.845 135.760 183.705 ;
        RECT 136.250 183.595 136.750 183.705 ;
        RECT 139.750 183.960 140.250 184.070 ;
        RECT 140.740 183.960 140.970 195.820 ;
        RECT 143.030 183.960 143.260 195.820 ;
        RECT 149.250 194.470 149.750 194.970 ;
        RECT 149.370 194.235 149.630 194.470 ;
        RECT 149.020 194.005 149.980 194.235 ;
        RECT 149.370 193.990 149.630 194.005 ;
        RECT 143.750 183.960 144.250 184.070 ;
        RECT 139.750 183.680 140.995 183.960 ;
        RECT 143.005 183.680 144.250 183.960 ;
        RECT 139.750 183.570 140.250 183.680 ;
        RECT 96.750 181.485 97.250 181.595 ;
        RECT 99.750 181.485 100.250 181.595 ;
        RECT 96.750 181.205 100.250 181.485 ;
        RECT 96.750 181.095 97.250 181.205 ;
        RECT 99.750 181.095 100.250 181.205 ;
        RECT 104.250 181.485 104.750 181.595 ;
        RECT 107.250 181.485 107.750 181.595 ;
        RECT 104.250 181.205 107.750 181.485 ;
        RECT 104.250 181.095 104.750 181.205 ;
        RECT 107.250 181.095 107.750 181.205 ;
        RECT 111.750 181.485 112.250 181.595 ;
        RECT 114.750 181.485 115.250 181.595 ;
        RECT 111.750 181.205 115.250 181.485 ;
        RECT 111.750 181.095 112.250 181.205 ;
        RECT 114.750 181.095 115.250 181.205 ;
        RECT 119.250 181.485 119.750 181.595 ;
        RECT 122.250 181.485 122.750 181.595 ;
        RECT 119.250 181.205 122.750 181.485 ;
        RECT 119.250 181.095 119.750 181.205 ;
        RECT 122.250 181.095 122.750 181.205 ;
        RECT 126.750 181.510 127.250 181.620 ;
        RECT 129.750 181.510 130.250 181.620 ;
        RECT 126.750 181.230 130.250 181.510 ;
        RECT 126.750 181.120 127.250 181.230 ;
        RECT 129.750 181.120 130.250 181.230 ;
        RECT 134.250 181.510 134.750 181.620 ;
        RECT 137.250 181.510 137.750 181.620 ;
        RECT 134.250 181.230 137.750 181.510 ;
        RECT 134.250 181.120 134.750 181.230 ;
        RECT 137.250 181.120 137.750 181.230 ;
        RECT 140.740 171.820 140.970 183.680 ;
        RECT 143.030 171.820 143.260 183.680 ;
        RECT 143.750 183.570 144.250 183.680 ;
        RECT 147.250 183.985 147.750 184.095 ;
        RECT 148.740 183.985 148.970 193.845 ;
        RECT 150.030 183.985 150.260 193.845 ;
        RECT 151.250 183.985 151.750 184.095 ;
        RECT 147.250 183.705 148.995 183.985 ;
        RECT 150.005 183.705 151.750 183.985 ;
        RECT 147.250 183.595 147.750 183.705 ;
        RECT 148.740 173.845 148.970 183.705 ;
        RECT 150.030 173.845 150.260 183.705 ;
        RECT 151.250 183.595 151.750 183.705 ;
        RECT 149.250 173.510 149.750 173.620 ;
        RECT 152.250 173.510 152.750 173.620 ;
        RECT 149.250 173.230 152.750 173.510 ;
        RECT 149.250 173.120 149.750 173.230 ;
        RECT 152.250 173.120 152.750 173.230 ;
        RECT 141.750 171.485 142.250 171.595 ;
        RECT 144.750 171.485 145.250 171.595 ;
        RECT 141.750 171.205 145.250 171.485 ;
        RECT 141.750 171.095 142.250 171.205 ;
        RECT 144.750 171.095 145.250 171.205 ;
        RECT 86.250 152.500 86.750 153.000 ;
        RECT 86.300 133.000 86.700 152.500 ;
        RECT 86.250 132.500 86.750 133.000 ;
        RECT 86.300 113.000 86.700 132.500 ;
        RECT 86.250 112.500 86.750 113.000 ;
        RECT 86.300 93.000 86.700 112.500 ;
        RECT 86.250 92.500 86.750 93.000 ;
        RECT 86.300 74.250 86.700 92.500 ;
        RECT 86.250 73.750 86.750 74.250 ;
        RECT 78.750 71.350 79.250 71.850 ;
        RECT 71.250 70.150 71.750 70.650 ;
        RECT 63.750 68.950 64.250 69.450 ;
        RECT 64.750 69.045 65.250 69.155 ;
        RECT 65.875 69.045 66.125 69.050 ;
        RECT 56.250 67.750 56.750 68.250 ;
        RECT 48.750 7.750 49.250 8.250 ;
        RECT 41.250 5.750 41.750 6.250 ;
        RECT 33.750 3.750 34.250 4.250 ;
        RECT 33.800 2.800 34.200 3.750 ;
        RECT 41.300 2.800 41.700 5.750 ;
        RECT 48.800 2.800 49.200 7.750 ;
        RECT 56.300 2.800 56.700 67.750 ;
        RECT 63.800 2.800 64.200 68.950 ;
        RECT 64.750 68.765 66.140 69.045 ;
        RECT 64.750 68.655 65.250 68.765 ;
        RECT 65.875 66.945 66.125 68.765 ;
        RECT 65.875 51.235 66.125 53.055 ;
        RECT 66.750 51.235 67.250 51.345 ;
        RECT 65.860 50.955 67.250 51.235 ;
        RECT 65.875 50.950 66.125 50.955 ;
        RECT 66.750 50.845 67.250 50.955 ;
        RECT 65.750 50.495 66.250 50.605 ;
        RECT 68.250 50.495 68.750 50.605 ;
        RECT 65.750 50.215 68.750 50.495 ;
        RECT 65.750 50.105 66.250 50.215 ;
        RECT 68.250 50.105 68.750 50.215 ;
        RECT 71.300 2.800 71.700 70.150 ;
        RECT 78.800 2.800 79.200 71.350 ;
        RECT 86.300 2.800 86.700 73.750 ;
        RECT 88.750 59.045 89.250 59.155 ;
        RECT 89.875 59.045 90.125 59.050 ;
        RECT 108.750 59.045 109.250 59.155 ;
        RECT 109.875 59.045 110.125 59.050 ;
        RECT 88.750 58.765 90.140 59.045 ;
        RECT 108.750 58.765 110.140 59.045 ;
        RECT 88.750 58.655 89.250 58.765 ;
        RECT 89.875 56.945 90.125 58.765 ;
        RECT 108.750 58.655 109.250 58.765 ;
        RECT 109.875 56.945 110.125 58.765 ;
        RECT 89.875 25.235 90.125 27.055 ;
        RECT 90.750 25.235 91.250 25.345 ;
        RECT 109.875 25.235 110.125 27.055 ;
        RECT 110.750 25.235 111.250 25.345 ;
        RECT 89.860 24.955 91.250 25.235 ;
        RECT 109.860 24.955 111.250 25.235 ;
        RECT 89.875 24.950 90.125 24.955 ;
        RECT 90.750 24.845 91.250 24.955 ;
        RECT 109.875 24.950 110.125 24.955 ;
        RECT 110.750 24.845 111.250 24.955 ;
        RECT 89.750 24.495 90.250 24.605 ;
        RECT 92.250 24.495 92.750 24.605 ;
        RECT 89.750 24.215 92.750 24.495 ;
        RECT 89.750 24.105 90.250 24.215 ;
        RECT 92.250 24.105 92.750 24.215 ;
        RECT 109.750 24.495 110.250 24.605 ;
        RECT 112.250 24.495 112.750 24.605 ;
        RECT 109.750 24.215 112.750 24.495 ;
        RECT 109.750 24.105 110.250 24.215 ;
        RECT 112.250 24.105 112.750 24.215 ;
      LAYER met2 ;
        RECT 133.240 224.700 133.840 225.300 ;
        RECT 135.400 224.700 136.000 225.300 ;
        RECT 138.160 224.700 138.760 225.300 ;
        RECT 41.200 219.700 41.800 220.300 ;
        RECT 119.200 219.700 119.800 220.300 ;
        RECT 78.700 218.700 79.300 219.300 ;
        RECT 71.200 217.700 71.800 218.300 ;
        RECT 109.700 217.700 110.300 218.300 ;
        RECT 102.200 216.700 102.800 217.300 ;
        RECT 63.700 214.700 64.300 215.300 ;
        RECT 56.200 213.700 56.800 214.300 ;
        RECT 94.700 213.700 95.300 214.300 ;
        RECT 96.700 213.700 97.300 214.300 ;
        RECT 26.200 212.700 26.800 213.300 ;
        RECT 82.700 212.700 83.300 213.300 ;
        RECT 91.200 212.700 91.800 213.300 ;
        RECT 18.700 210.700 19.300 211.300 ;
        RECT 52.700 210.700 53.300 211.300 ;
        RECT 61.200 210.700 61.800 211.300 ;
        RECT 67.700 210.700 68.300 211.300 ;
        RECT 76.200 210.700 76.800 211.300 ;
        RECT 80.700 210.700 81.300 211.300 ;
        RECT 48.700 209.700 49.300 210.300 ;
        RECT 33.700 208.700 34.300 209.300 ;
        RECT 50.700 208.700 51.300 209.300 ;
        RECT 35.700 207.700 36.300 208.300 ;
        RECT 43.200 207.700 43.800 208.300 ;
        RECT 20.700 206.700 21.300 207.300 ;
        RECT 28.200 206.700 28.800 207.300 ;
        RECT 5.700 205.700 6.300 206.300 ;
        RECT 13.200 205.700 13.800 206.300 ;
        RECT 5.800 184.095 6.200 205.700 ;
        RECT 6.700 202.700 7.300 203.300 ;
        RECT 6.800 185.470 7.200 202.700 ;
        RECT 7.700 200.700 8.300 201.300 ;
        RECT 9.700 200.700 10.300 201.300 ;
        RECT 6.750 184.970 7.250 185.470 ;
        RECT 7.800 184.095 8.200 200.700 ;
        RECT 5.750 183.595 6.250 184.095 ;
        RECT 7.750 183.595 8.250 184.095 ;
        RECT 9.800 183.120 10.200 200.700 ;
        RECT 13.300 184.070 13.700 205.700 ;
        RECT 14.200 202.700 14.800 203.300 ;
        RECT 14.300 185.990 14.700 202.700 ;
        RECT 15.200 201.700 15.800 202.300 ;
        RECT 17.200 201.700 17.800 202.300 ;
        RECT 14.250 185.490 14.750 185.990 ;
        RECT 15.300 184.070 15.700 201.700 ;
        RECT 13.250 183.570 13.750 184.070 ;
        RECT 15.250 183.570 15.750 184.070 ;
        RECT 9.750 182.620 10.250 183.120 ;
        RECT 17.300 182.595 17.700 201.700 ;
        RECT 20.800 184.095 21.200 206.700 ;
        RECT 21.700 203.700 22.300 204.300 ;
        RECT 21.800 185.470 22.200 203.700 ;
        RECT 22.700 200.700 23.300 201.300 ;
        RECT 24.700 200.700 25.300 201.300 ;
        RECT 21.750 184.970 22.250 185.470 ;
        RECT 22.800 184.095 23.200 200.700 ;
        RECT 20.750 183.595 21.250 184.095 ;
        RECT 22.750 183.595 23.250 184.095 ;
        RECT 24.800 183.120 25.200 200.700 ;
        RECT 28.300 184.070 28.700 206.700 ;
        RECT 29.200 203.700 29.800 204.300 ;
        RECT 29.300 185.990 29.700 203.700 ;
        RECT 30.200 201.700 30.800 202.300 ;
        RECT 32.200 201.700 32.800 202.300 ;
        RECT 29.250 185.490 29.750 185.990 ;
        RECT 30.300 184.070 30.700 201.700 ;
        RECT 28.250 183.570 28.750 184.070 ;
        RECT 30.250 183.570 30.750 184.070 ;
        RECT 24.750 182.620 25.250 183.120 ;
        RECT 32.300 182.595 32.700 201.700 ;
        RECT 35.800 184.095 36.200 207.700 ;
        RECT 36.700 204.700 37.300 205.300 ;
        RECT 36.800 185.470 37.200 204.700 ;
        RECT 37.700 200.700 38.300 201.300 ;
        RECT 39.700 200.700 40.300 201.300 ;
        RECT 36.750 184.970 37.250 185.470 ;
        RECT 37.800 184.095 38.200 200.700 ;
        RECT 35.750 183.595 36.250 184.095 ;
        RECT 37.750 183.595 38.250 184.095 ;
        RECT 39.800 183.120 40.200 200.700 ;
        RECT 43.300 184.070 43.700 207.700 ;
        RECT 44.200 204.700 44.800 205.300 ;
        RECT 44.300 185.990 44.700 204.700 ;
        RECT 45.200 201.700 45.800 202.300 ;
        RECT 47.200 201.700 47.800 202.300 ;
        RECT 44.250 185.490 44.750 185.990 ;
        RECT 45.300 184.070 45.700 201.700 ;
        RECT 43.250 183.570 43.750 184.070 ;
        RECT 45.250 183.570 45.750 184.070 ;
        RECT 39.750 182.620 40.250 183.120 ;
        RECT 47.300 182.595 47.700 201.700 ;
        RECT 50.800 184.095 51.200 208.700 ;
        RECT 51.700 202.700 52.300 203.300 ;
        RECT 51.800 185.470 52.200 202.700 ;
        RECT 51.750 184.970 52.250 185.470 ;
        RECT 52.800 184.095 53.200 210.700 ;
        RECT 57.200 208.700 57.800 209.300 ;
        RECT 54.700 200.700 55.300 201.300 ;
        RECT 50.750 183.595 51.250 184.095 ;
        RECT 52.750 183.595 53.250 184.095 ;
        RECT 54.800 183.120 55.200 200.700 ;
        RECT 57.300 184.070 57.700 208.700 ;
        RECT 59.200 205.700 59.800 206.300 ;
        RECT 59.300 185.990 59.700 205.700 ;
        RECT 59.250 185.490 59.750 185.990 ;
        RECT 61.300 184.070 61.700 210.700 ;
        RECT 65.700 209.700 66.300 210.300 ;
        RECT 62.200 201.700 62.800 202.300 ;
        RECT 57.250 183.570 57.750 184.070 ;
        RECT 61.250 183.570 61.750 184.070 ;
        RECT 54.750 182.620 55.250 183.120 ;
        RECT 62.300 182.595 62.700 201.700 ;
        RECT 65.800 184.095 66.200 209.700 ;
        RECT 66.700 203.700 67.300 204.300 ;
        RECT 66.800 185.470 67.200 203.700 ;
        RECT 66.750 184.970 67.250 185.470 ;
        RECT 67.800 184.095 68.200 210.700 ;
        RECT 72.200 209.700 72.800 210.300 ;
        RECT 69.700 200.700 70.300 201.300 ;
        RECT 65.750 183.595 66.250 184.095 ;
        RECT 67.750 183.595 68.250 184.095 ;
        RECT 69.800 183.120 70.200 200.700 ;
        RECT 72.300 184.070 72.700 209.700 ;
        RECT 74.200 206.700 74.800 207.300 ;
        RECT 74.300 185.990 74.700 206.700 ;
        RECT 74.250 185.490 74.750 185.990 ;
        RECT 76.300 184.070 76.700 210.700 ;
        RECT 77.200 201.700 77.800 202.300 ;
        RECT 72.250 183.570 72.750 184.070 ;
        RECT 76.250 183.570 76.750 184.070 ;
        RECT 69.750 182.620 70.250 183.120 ;
        RECT 77.300 182.595 77.700 201.700 ;
        RECT 80.800 184.095 81.200 210.700 ;
        RECT 81.700 204.700 82.300 205.300 ;
        RECT 81.800 185.470 82.200 204.700 ;
        RECT 81.750 184.970 82.250 185.470 ;
        RECT 82.800 184.095 83.200 212.700 ;
        RECT 87.200 210.700 87.800 211.300 ;
        RECT 84.700 200.700 85.300 201.300 ;
        RECT 86.200 200.700 86.800 201.300 ;
        RECT 80.750 183.595 81.250 184.095 ;
        RECT 82.750 183.595 83.250 184.095 ;
        RECT 84.800 183.120 85.200 200.700 ;
        RECT 87.300 184.070 87.700 210.700 ;
        RECT 89.200 207.700 89.800 208.300 ;
        RECT 89.300 185.990 89.700 207.700 ;
        RECT 89.250 185.490 89.750 185.990 ;
        RECT 91.300 184.070 91.700 212.700 ;
        RECT 92.200 201.700 92.800 202.300 ;
        RECT 87.250 183.570 87.750 184.070 ;
        RECT 91.250 183.570 91.750 184.070 ;
        RECT 84.750 182.620 85.250 183.120 ;
        RECT 92.300 182.595 92.700 201.700 ;
        RECT 94.800 184.070 95.200 213.700 ;
        RECT 96.800 186.990 97.200 213.700 ;
        RECT 98.700 201.700 99.300 202.300 ;
        RECT 99.700 201.700 100.300 202.300 ;
        RECT 96.750 186.490 97.250 186.990 ;
        RECT 98.800 184.070 99.200 201.700 ;
        RECT 94.750 183.570 95.250 184.070 ;
        RECT 98.750 183.570 99.250 184.070 ;
        RECT 17.250 182.095 17.750 182.595 ;
        RECT 32.250 182.095 32.750 182.595 ;
        RECT 47.250 182.095 47.750 182.595 ;
        RECT 62.250 182.095 62.750 182.595 ;
        RECT 77.250 182.095 77.750 182.595 ;
        RECT 92.250 182.095 92.750 182.595 ;
        RECT 99.800 181.595 100.200 201.700 ;
        RECT 102.300 184.070 102.700 216.700 ;
        RECT 104.200 213.700 104.800 214.300 ;
        RECT 104.300 186.990 104.700 213.700 ;
        RECT 106.200 201.700 106.800 202.300 ;
        RECT 107.200 201.700 107.800 202.300 ;
        RECT 104.250 186.490 104.750 186.990 ;
        RECT 106.300 184.070 106.700 201.700 ;
        RECT 102.250 183.570 102.750 184.070 ;
        RECT 106.250 183.570 106.750 184.070 ;
        RECT 107.300 181.595 107.700 201.700 ;
        RECT 109.800 184.070 110.200 217.700 ;
        RECT 113.700 216.700 114.300 217.300 ;
        RECT 111.700 212.700 112.300 213.300 ;
        RECT 111.800 186.990 112.200 212.700 ;
        RECT 111.750 186.490 112.250 186.990 ;
        RECT 113.800 184.070 114.200 216.700 ;
        RECT 117.200 215.700 117.800 216.300 ;
        RECT 114.700 201.700 115.300 202.300 ;
        RECT 109.750 183.570 110.250 184.070 ;
        RECT 113.750 183.570 114.250 184.070 ;
        RECT 114.800 181.595 115.200 201.700 ;
        RECT 117.300 184.070 117.700 215.700 ;
        RECT 119.300 186.990 119.700 219.700 ;
        RECT 132.200 217.700 132.800 218.300 ;
        RECT 121.200 216.700 121.800 217.300 ;
        RECT 119.250 186.490 119.750 186.990 ;
        RECT 121.300 184.070 121.700 216.700 ;
        RECT 124.700 215.700 125.300 216.300 ;
        RECT 126.700 215.700 127.300 216.300 ;
        RECT 122.200 201.700 122.800 202.300 ;
        RECT 117.250 183.570 117.750 184.070 ;
        RECT 121.250 183.570 121.750 184.070 ;
        RECT 122.300 181.595 122.700 201.700 ;
        RECT 124.800 184.095 125.200 215.700 ;
        RECT 126.800 186.970 127.200 215.700 ;
        RECT 128.700 200.700 129.300 201.300 ;
        RECT 129.700 200.700 130.300 201.300 ;
        RECT 126.750 186.470 127.250 186.970 ;
        RECT 128.800 184.095 129.200 200.700 ;
        RECT 124.750 183.595 125.250 184.095 ;
        RECT 128.750 183.595 129.250 184.095 ;
        RECT 129.800 181.620 130.200 200.700 ;
        RECT 132.300 184.095 132.700 217.700 ;
        RECT 133.340 205.300 133.740 224.700 ;
        RECT 134.200 215.700 134.800 216.300 ;
        RECT 133.240 204.700 133.840 205.300 ;
        RECT 134.300 186.970 134.700 215.700 ;
        RECT 135.500 204.300 135.900 224.700 ;
        RECT 135.400 203.700 136.000 204.300 ;
        RECT 138.260 203.300 138.660 224.700 ;
        RECT 139.700 219.700 140.300 220.300 ;
        RECT 147.200 219.700 147.800 220.300 ;
        RECT 138.160 202.700 138.760 203.300 ;
        RECT 136.200 200.700 136.800 201.300 ;
        RECT 137.200 200.700 137.800 201.300 ;
        RECT 134.250 186.470 134.750 186.970 ;
        RECT 136.300 184.095 136.700 200.700 ;
        RECT 132.250 183.595 132.750 184.095 ;
        RECT 136.250 183.595 136.750 184.095 ;
        RECT 137.300 181.620 137.700 200.700 ;
        RECT 139.800 184.070 140.200 219.700 ;
        RECT 141.700 213.700 142.300 214.300 ;
        RECT 141.800 196.990 142.200 213.700 ;
        RECT 143.700 201.700 144.300 202.300 ;
        RECT 144.700 201.700 145.300 202.300 ;
        RECT 141.750 196.490 142.250 196.990 ;
        RECT 143.800 184.070 144.200 201.700 ;
        RECT 139.750 183.570 140.250 184.070 ;
        RECT 143.750 183.570 144.250 184.070 ;
        RECT 99.750 181.095 100.250 181.595 ;
        RECT 107.250 181.095 107.750 181.595 ;
        RECT 114.750 181.095 115.250 181.595 ;
        RECT 122.250 181.095 122.750 181.595 ;
        RECT 129.750 181.120 130.250 181.620 ;
        RECT 137.250 181.120 137.750 181.620 ;
        RECT 144.800 171.595 145.200 201.700 ;
        RECT 147.300 184.095 147.700 219.700 ;
        RECT 149.200 217.700 149.800 218.300 ;
        RECT 149.300 194.970 149.700 217.700 ;
        RECT 151.200 200.700 151.800 201.300 ;
        RECT 152.200 200.700 152.800 201.300 ;
        RECT 149.250 194.470 149.750 194.970 ;
        RECT 151.300 184.095 151.700 200.700 ;
        RECT 147.250 183.595 147.750 184.095 ;
        RECT 151.250 183.595 151.750 184.095 ;
        RECT 152.300 173.620 152.700 200.700 ;
        RECT 152.250 173.120 152.750 173.620 ;
        RECT 144.750 171.095 145.250 171.595 ;
        RECT 26.250 153.700 26.750 153.750 ;
        RECT 30.120 153.700 30.720 153.800 ;
        RECT 48.620 153.700 49.220 153.800 ;
        RECT 104.120 153.700 104.720 153.800 ;
        RECT 122.620 153.700 123.220 153.800 ;
        RECT 11.720 153.300 141.620 153.700 ;
        RECT 26.250 153.250 26.750 153.300 ;
        RECT 30.120 153.200 30.720 153.300 ;
        RECT 48.620 153.200 49.220 153.300 ;
        RECT 104.120 153.200 104.720 153.300 ;
        RECT 122.620 153.200 123.220 153.300 ;
        RECT 86.250 152.950 86.750 153.000 ;
        RECT 1.800 152.550 151.200 152.950 ;
        RECT 86.250 152.500 86.750 152.550 ;
        RECT 11.620 152.200 12.220 152.300 ;
        RECT 18.750 152.200 19.250 152.250 ;
        RECT 67.120 152.200 67.720 152.300 ;
        RECT 85.620 152.200 86.220 152.300 ;
        RECT 141.120 152.200 141.720 152.300 ;
        RECT 11.620 151.800 141.720 152.200 ;
        RECT 11.620 151.700 12.220 151.800 ;
        RECT 18.750 151.750 19.250 151.800 ;
        RECT 67.120 151.700 67.720 151.800 ;
        RECT 85.620 151.700 86.220 151.800 ;
        RECT 141.120 151.700 141.720 151.800 ;
        RECT 11.620 133.700 12.220 133.800 ;
        RECT 26.250 133.700 26.750 133.750 ;
        RECT 67.120 133.700 67.720 133.800 ;
        RECT 85.620 133.700 86.220 133.800 ;
        RECT 141.120 133.700 141.720 133.800 ;
        RECT 11.620 133.300 141.720 133.700 ;
        RECT 11.620 133.200 12.220 133.300 ;
        RECT 26.250 133.250 26.750 133.300 ;
        RECT 67.120 133.200 67.720 133.300 ;
        RECT 85.620 133.200 86.220 133.300 ;
        RECT 141.120 133.200 141.720 133.300 ;
        RECT 86.250 132.950 86.750 133.000 ;
        RECT 1.800 132.550 151.200 132.950 ;
        RECT 86.250 132.500 86.750 132.550 ;
        RECT 18.750 132.200 19.250 132.250 ;
        RECT 30.120 132.200 30.720 132.300 ;
        RECT 48.620 132.200 49.220 132.300 ;
        RECT 104.120 132.200 104.720 132.300 ;
        RECT 122.620 132.200 123.220 132.300 ;
        RECT 11.720 131.800 141.620 132.200 ;
        RECT 18.750 131.750 19.250 131.800 ;
        RECT 30.120 131.700 30.720 131.800 ;
        RECT 48.620 131.700 49.220 131.800 ;
        RECT 104.120 131.700 104.720 131.800 ;
        RECT 122.620 131.700 123.220 131.800 ;
        RECT 11.620 113.700 12.220 113.800 ;
        RECT 26.250 113.700 26.750 113.750 ;
        RECT 67.120 113.700 67.720 113.800 ;
        RECT 85.620 113.700 86.220 113.800 ;
        RECT 141.120 113.700 141.720 113.800 ;
        RECT 11.620 113.300 141.720 113.700 ;
        RECT 11.620 113.200 12.220 113.300 ;
        RECT 26.250 113.250 26.750 113.300 ;
        RECT 67.120 113.200 67.720 113.300 ;
        RECT 85.620 113.200 86.220 113.300 ;
        RECT 141.120 113.200 141.720 113.300 ;
        RECT 86.250 112.950 86.750 113.000 ;
        RECT 1.800 112.550 151.200 112.950 ;
        RECT 86.250 112.500 86.750 112.550 ;
        RECT 18.750 112.200 19.250 112.250 ;
        RECT 30.120 112.200 30.720 112.300 ;
        RECT 48.620 112.200 49.220 112.300 ;
        RECT 104.120 112.200 104.720 112.300 ;
        RECT 122.620 112.200 123.220 112.300 ;
        RECT 11.720 111.800 141.620 112.200 ;
        RECT 18.750 111.750 19.250 111.800 ;
        RECT 30.120 111.700 30.720 111.800 ;
        RECT 48.620 111.700 49.220 111.800 ;
        RECT 104.120 111.700 104.720 111.800 ;
        RECT 122.620 111.700 123.220 111.800 ;
        RECT 26.250 93.700 26.750 93.750 ;
        RECT 30.120 93.700 30.720 93.800 ;
        RECT 48.620 93.700 49.220 93.800 ;
        RECT 104.120 93.700 104.720 93.800 ;
        RECT 122.620 93.700 123.220 93.800 ;
        RECT 11.720 93.300 141.620 93.700 ;
        RECT 26.250 93.250 26.750 93.300 ;
        RECT 30.120 93.200 30.720 93.300 ;
        RECT 48.620 93.200 49.220 93.300 ;
        RECT 104.120 93.200 104.720 93.300 ;
        RECT 122.620 93.200 123.220 93.300 ;
        RECT 86.250 92.950 86.750 93.000 ;
        RECT 1.800 92.550 151.200 92.950 ;
        RECT 86.250 92.500 86.750 92.550 ;
        RECT 11.620 92.200 12.220 92.300 ;
        RECT 18.750 92.200 19.250 92.250 ;
        RECT 67.120 92.200 67.720 92.300 ;
        RECT 85.620 92.200 86.220 92.300 ;
        RECT 141.120 92.200 141.720 92.300 ;
        RECT 11.620 91.800 141.720 92.200 ;
        RECT 11.620 91.700 12.220 91.800 ;
        RECT 18.750 91.750 19.250 91.800 ;
        RECT 67.120 91.700 67.720 91.800 ;
        RECT 85.620 91.700 86.220 91.800 ;
        RECT 141.120 91.700 141.720 91.800 ;
        RECT 68.200 73.700 68.800 74.300 ;
        RECT 86.200 73.700 86.800 74.300 ;
        RECT 92.200 73.700 92.800 74.300 ;
        RECT 110.700 73.700 111.300 74.300 ;
        RECT 112.200 73.700 112.800 74.300 ;
        RECT 41.200 72.500 41.800 73.100 ;
        RECT 45.520 72.500 46.120 73.100 ;
        RECT 30.820 71.300 31.420 71.900 ;
        RECT 30.920 56.300 31.320 71.300 ;
        RECT 30.820 55.700 31.420 56.300 ;
        RECT 45.620 21.300 46.020 72.500 ;
        RECT 66.700 71.300 67.300 71.900 ;
        RECT 64.700 70.100 65.300 70.700 ;
        RECT 63.700 68.900 64.300 69.500 ;
        RECT 64.800 69.155 65.200 70.100 ;
        RECT 64.750 68.655 65.250 69.155 ;
        RECT 56.200 67.700 56.800 68.300 ;
        RECT 66.800 51.345 67.200 71.300 ;
        RECT 66.750 50.845 67.250 51.345 ;
        RECT 68.300 50.605 68.700 73.700 ;
        RECT 78.700 71.300 79.300 71.900 ;
        RECT 71.200 70.100 71.800 70.700 ;
        RECT 90.700 68.900 91.300 69.500 ;
        RECT 88.700 67.700 89.300 68.300 ;
        RECT 88.800 59.155 89.200 67.700 ;
        RECT 88.750 58.655 89.250 59.155 ;
        RECT 68.250 50.105 68.750 50.605 ;
        RECT 90.800 25.345 91.200 68.900 ;
        RECT 90.750 24.845 91.250 25.345 ;
        RECT 92.300 24.605 92.700 73.700 ;
        RECT 108.700 68.900 109.300 69.500 ;
        RECT 108.800 59.155 109.200 68.900 ;
        RECT 108.750 58.655 109.250 59.155 ;
        RECT 110.800 25.345 111.200 73.700 ;
        RECT 110.750 24.845 111.250 25.345 ;
        RECT 112.300 24.605 112.700 73.700 ;
        RECT 92.250 24.105 92.750 24.605 ;
        RECT 112.250 24.105 112.750 24.605 ;
        RECT 45.520 20.700 46.120 21.300 ;
        RECT 48.700 7.700 49.300 8.300 ;
        RECT 113.320 7.700 113.920 8.300 ;
        RECT 41.200 5.700 41.800 6.300 ;
        RECT 33.700 3.700 34.300 4.300 ;
        RECT 113.420 1.050 113.820 7.700 ;
        RECT 132.640 5.700 133.240 6.300 ;
        RECT 132.740 1.050 133.140 5.700 ;
        RECT 151.960 3.700 152.560 4.300 ;
        RECT 152.060 1.050 152.460 3.700 ;
        RECT 113.320 0.450 113.920 1.050 ;
        RECT 132.640 0.450 133.240 1.050 ;
        RECT 151.960 0.450 152.560 1.050 ;
      LAYER met3 ;
        RECT 30.420 224.600 31.220 225.400 ;
        RECT 33.180 224.600 33.980 225.400 ;
        RECT 35.940 224.600 36.740 225.400 ;
        RECT 38.700 224.600 39.500 225.400 ;
        RECT 41.460 224.600 42.260 225.400 ;
        RECT 44.220 224.600 45.020 225.400 ;
        RECT 46.980 224.600 47.780 225.400 ;
        RECT 49.740 224.600 50.540 225.400 ;
        RECT 52.500 224.600 53.300 225.400 ;
        RECT 55.260 224.600 56.060 225.400 ;
        RECT 58.020 224.600 58.820 225.400 ;
        RECT 60.780 224.600 61.580 225.400 ;
        RECT 63.540 224.600 64.340 225.400 ;
        RECT 66.300 224.600 67.100 225.400 ;
        RECT 69.060 224.600 69.860 225.400 ;
        RECT 71.820 224.600 72.620 225.400 ;
        RECT 74.580 224.600 75.380 225.400 ;
        RECT 77.340 224.600 78.140 225.400 ;
        RECT 80.100 224.600 80.900 225.400 ;
        RECT 82.860 224.600 83.660 225.400 ;
        RECT 85.620 224.600 86.420 225.400 ;
        RECT 88.380 224.600 89.180 225.400 ;
        RECT 91.140 224.600 91.940 225.400 ;
        RECT 93.900 224.600 94.700 225.400 ;
        RECT 132.540 225.300 133.340 225.400 ;
        RECT 132.540 224.700 133.840 225.300 ;
        RECT 132.540 224.600 133.340 224.700 ;
        RECT 135.300 224.600 136.100 225.400 ;
        RECT 138.060 224.600 138.860 225.400 ;
        RECT 1.600 223.725 2.400 223.900 ;
        RECT 30.595 223.725 31.045 224.600 ;
        RECT 33.355 223.725 33.805 224.600 ;
        RECT 36.115 223.725 36.565 224.600 ;
        RECT 38.875 223.725 39.325 224.600 ;
        RECT 41.635 223.725 42.085 224.600 ;
        RECT 44.395 223.725 44.845 224.600 ;
        RECT 47.155 223.725 47.605 224.600 ;
        RECT 49.915 223.725 50.365 224.600 ;
        RECT 52.675 223.725 53.125 224.600 ;
        RECT 55.435 223.725 55.885 224.600 ;
        RECT 58.195 223.725 58.645 224.600 ;
        RECT 60.955 223.725 61.405 224.600 ;
        RECT 63.715 223.725 64.165 224.600 ;
        RECT 66.475 223.725 66.925 224.600 ;
        RECT 69.235 223.725 69.685 224.600 ;
        RECT 71.995 223.725 72.445 224.600 ;
        RECT 74.755 223.725 75.205 224.600 ;
        RECT 77.515 223.725 77.965 224.600 ;
        RECT 80.275 223.725 80.725 224.600 ;
        RECT 83.035 223.725 83.485 224.600 ;
        RECT 85.795 223.725 86.245 224.600 ;
        RECT 88.555 223.725 89.005 224.600 ;
        RECT 91.315 223.725 91.765 224.600 ;
        RECT 94.075 223.725 94.525 224.600 ;
        RECT 1.600 223.275 153.225 223.725 ;
        RECT 1.600 223.100 2.400 223.275 ;
        RECT 41.200 220.225 41.800 220.300 ;
        RECT 119.200 220.225 119.800 220.300 ;
        RECT 139.700 220.225 140.300 220.300 ;
        RECT 147.200 220.225 147.800 220.300 ;
        RECT 1.775 219.775 159.225 220.225 ;
        RECT 41.200 219.700 41.800 219.775 ;
        RECT 119.200 219.700 119.800 219.775 ;
        RECT 139.700 219.700 140.300 219.775 ;
        RECT 147.200 219.700 147.800 219.775 ;
        RECT 78.700 219.225 79.300 219.300 ;
        RECT 1.775 218.775 159.225 219.225 ;
        RECT 78.700 218.700 79.300 218.775 ;
        RECT 71.200 218.225 71.800 218.300 ;
        RECT 109.700 218.225 110.300 218.300 ;
        RECT 132.200 218.225 132.800 218.300 ;
        RECT 149.200 218.225 149.800 218.300 ;
        RECT 1.775 217.775 159.225 218.225 ;
        RECT 71.200 217.700 71.800 217.775 ;
        RECT 109.700 217.700 110.300 217.775 ;
        RECT 132.200 217.700 132.800 217.775 ;
        RECT 149.200 217.700 149.800 217.775 ;
        RECT 102.200 217.225 102.800 217.300 ;
        RECT 113.700 217.225 114.300 217.300 ;
        RECT 121.200 217.225 121.800 217.300 ;
        RECT 1.775 216.775 159.225 217.225 ;
        RECT 102.200 216.700 102.800 216.775 ;
        RECT 113.700 216.700 114.300 216.775 ;
        RECT 121.200 216.700 121.800 216.775 ;
        RECT 117.200 216.225 117.800 216.300 ;
        RECT 124.700 216.225 125.300 216.300 ;
        RECT 126.700 216.225 127.300 216.300 ;
        RECT 134.200 216.225 134.800 216.300 ;
        RECT 1.775 215.775 159.225 216.225 ;
        RECT 117.200 215.700 117.800 215.775 ;
        RECT 124.700 215.700 125.300 215.775 ;
        RECT 126.700 215.700 127.300 215.775 ;
        RECT 134.200 215.700 134.800 215.775 ;
        RECT 63.700 215.225 64.300 215.300 ;
        RECT 1.775 214.775 159.225 215.225 ;
        RECT 63.700 214.700 64.300 214.775 ;
        RECT 56.200 214.225 56.800 214.300 ;
        RECT 94.700 214.225 95.300 214.300 ;
        RECT 96.700 214.225 97.300 214.300 ;
        RECT 104.200 214.225 104.800 214.300 ;
        RECT 141.700 214.225 142.300 214.300 ;
        RECT 1.775 213.775 159.225 214.225 ;
        RECT 56.200 213.700 56.800 213.775 ;
        RECT 94.700 213.700 95.300 213.775 ;
        RECT 96.700 213.700 97.300 213.775 ;
        RECT 104.200 213.700 104.800 213.775 ;
        RECT 141.700 213.700 142.300 213.775 ;
        RECT 26.200 213.225 26.800 213.300 ;
        RECT 82.700 213.225 83.300 213.300 ;
        RECT 91.200 213.225 91.800 213.300 ;
        RECT 111.700 213.225 112.300 213.300 ;
        RECT 1.775 212.775 159.225 213.225 ;
        RECT 26.200 212.700 26.800 212.775 ;
        RECT 82.700 212.700 83.300 212.775 ;
        RECT 91.200 212.700 91.800 212.775 ;
        RECT 111.700 212.700 112.300 212.775 ;
        RECT 1.600 212.225 2.400 212.400 ;
        RECT 1.600 211.775 159.225 212.225 ;
        RECT 1.600 211.600 2.400 211.775 ;
        RECT 18.700 211.225 19.300 211.300 ;
        RECT 52.700 211.225 53.300 211.300 ;
        RECT 61.200 211.225 61.800 211.300 ;
        RECT 67.700 211.225 68.300 211.300 ;
        RECT 76.200 211.225 76.800 211.300 ;
        RECT 80.700 211.225 81.300 211.300 ;
        RECT 87.200 211.225 87.800 211.300 ;
        RECT 1.775 210.775 159.225 211.225 ;
        RECT 18.700 210.700 19.300 210.775 ;
        RECT 52.700 210.700 53.300 210.775 ;
        RECT 61.200 210.700 61.800 210.775 ;
        RECT 67.700 210.700 68.300 210.775 ;
        RECT 76.200 210.700 76.800 210.775 ;
        RECT 80.700 210.700 81.300 210.775 ;
        RECT 87.200 210.700 87.800 210.775 ;
        RECT 48.700 210.225 49.300 210.300 ;
        RECT 65.700 210.225 66.300 210.300 ;
        RECT 72.200 210.225 72.800 210.300 ;
        RECT 1.775 209.775 159.225 210.225 ;
        RECT 48.700 209.700 49.300 209.775 ;
        RECT 65.700 209.700 66.300 209.775 ;
        RECT 72.200 209.700 72.800 209.775 ;
        RECT 33.700 209.225 34.300 209.300 ;
        RECT 50.700 209.225 51.300 209.300 ;
        RECT 57.200 209.225 57.800 209.300 ;
        RECT 1.775 208.775 159.225 209.225 ;
        RECT 33.700 208.700 34.300 208.775 ;
        RECT 50.700 208.700 51.300 208.775 ;
        RECT 57.200 208.700 57.800 208.775 ;
        RECT 35.700 208.225 36.300 208.300 ;
        RECT 43.200 208.225 43.800 208.300 ;
        RECT 89.200 208.225 89.800 208.300 ;
        RECT 1.775 207.775 159.225 208.225 ;
        RECT 35.700 207.700 36.300 207.775 ;
        RECT 43.200 207.700 43.800 207.775 ;
        RECT 89.200 207.700 89.800 207.775 ;
        RECT 20.700 207.225 21.300 207.300 ;
        RECT 28.200 207.225 28.800 207.300 ;
        RECT 74.200 207.225 74.800 207.300 ;
        RECT 1.775 206.775 159.225 207.225 ;
        RECT 20.700 206.700 21.300 206.775 ;
        RECT 28.200 206.700 28.800 206.775 ;
        RECT 74.200 206.700 74.800 206.775 ;
        RECT 5.700 206.225 6.300 206.300 ;
        RECT 13.200 206.225 13.800 206.300 ;
        RECT 59.200 206.225 59.800 206.300 ;
        RECT 1.775 205.775 159.225 206.225 ;
        RECT 5.700 205.700 6.300 205.775 ;
        RECT 13.200 205.700 13.800 205.775 ;
        RECT 59.200 205.700 59.800 205.775 ;
        RECT 36.700 205.225 37.300 205.300 ;
        RECT 44.200 205.225 44.800 205.300 ;
        RECT 81.700 205.225 82.300 205.300 ;
        RECT 133.240 205.225 133.840 205.300 ;
        RECT 35.775 204.775 140.225 205.225 ;
        RECT 36.700 204.700 37.300 204.775 ;
        RECT 44.200 204.700 44.800 204.775 ;
        RECT 81.700 204.700 82.300 204.775 ;
        RECT 133.240 204.700 133.840 204.775 ;
        RECT 21.700 204.225 22.300 204.300 ;
        RECT 29.200 204.225 29.800 204.300 ;
        RECT 66.700 204.225 67.300 204.300 ;
        RECT 135.400 204.225 136.000 204.300 ;
        RECT 20.775 203.775 140.225 204.225 ;
        RECT 21.700 203.700 22.300 203.775 ;
        RECT 29.200 203.700 29.800 203.775 ;
        RECT 66.700 203.700 67.300 203.775 ;
        RECT 135.400 203.700 136.000 203.775 ;
        RECT 6.700 203.225 7.300 203.300 ;
        RECT 14.200 203.225 14.800 203.300 ;
        RECT 51.700 203.225 52.300 203.300 ;
        RECT 138.160 203.225 138.760 203.300 ;
        RECT 5.775 202.775 140.225 203.225 ;
        RECT 6.700 202.700 7.300 202.775 ;
        RECT 14.200 202.700 14.800 202.775 ;
        RECT 51.700 202.700 52.300 202.775 ;
        RECT 138.160 202.700 138.760 202.775 ;
        RECT 15.200 202.225 15.800 202.300 ;
        RECT 17.200 202.225 17.800 202.300 ;
        RECT 30.200 202.225 30.800 202.300 ;
        RECT 32.200 202.225 32.800 202.300 ;
        RECT 45.200 202.225 45.800 202.300 ;
        RECT 47.200 202.225 47.800 202.300 ;
        RECT 62.200 202.225 62.800 202.300 ;
        RECT 77.200 202.225 77.800 202.300 ;
        RECT 92.200 202.225 92.800 202.300 ;
        RECT 98.700 202.225 99.300 202.300 ;
        RECT 99.700 202.225 100.300 202.300 ;
        RECT 106.200 202.225 106.800 202.300 ;
        RECT 107.200 202.225 107.800 202.300 ;
        RECT 114.700 202.225 115.300 202.300 ;
        RECT 122.200 202.225 122.800 202.300 ;
        RECT 143.700 202.225 144.300 202.300 ;
        RECT 144.700 202.225 145.300 202.300 ;
        RECT 158.600 202.225 159.400 202.400 ;
        RECT 1.775 201.775 159.400 202.225 ;
        RECT 15.200 201.700 15.800 201.775 ;
        RECT 17.200 201.700 17.800 201.775 ;
        RECT 30.200 201.700 30.800 201.775 ;
        RECT 32.200 201.700 32.800 201.775 ;
        RECT 45.200 201.700 45.800 201.775 ;
        RECT 47.200 201.700 47.800 201.775 ;
        RECT 62.200 201.700 62.800 201.775 ;
        RECT 77.200 201.700 77.800 201.775 ;
        RECT 92.200 201.700 92.800 201.775 ;
        RECT 98.700 201.700 99.300 201.775 ;
        RECT 99.700 201.700 100.300 201.775 ;
        RECT 106.200 201.700 106.800 201.775 ;
        RECT 107.200 201.700 107.800 201.775 ;
        RECT 114.700 201.700 115.300 201.775 ;
        RECT 122.200 201.700 122.800 201.775 ;
        RECT 143.700 201.700 144.300 201.775 ;
        RECT 144.700 201.700 145.300 201.775 ;
        RECT 158.600 201.600 159.400 201.775 ;
        RECT 1.600 201.225 2.400 201.400 ;
        RECT 7.700 201.225 8.300 201.300 ;
        RECT 9.700 201.225 10.300 201.300 ;
        RECT 22.700 201.225 23.300 201.300 ;
        RECT 24.700 201.225 25.300 201.300 ;
        RECT 37.700 201.225 38.300 201.300 ;
        RECT 39.700 201.225 40.300 201.300 ;
        RECT 54.700 201.225 55.300 201.300 ;
        RECT 69.700 201.225 70.300 201.300 ;
        RECT 84.700 201.225 85.300 201.300 ;
        RECT 86.200 201.225 86.800 201.300 ;
        RECT 128.700 201.225 129.300 201.300 ;
        RECT 129.700 201.225 130.300 201.300 ;
        RECT 136.200 201.225 136.800 201.300 ;
        RECT 137.200 201.225 137.800 201.300 ;
        RECT 151.200 201.225 151.800 201.300 ;
        RECT 152.200 201.225 152.800 201.300 ;
        RECT 1.600 200.775 159.225 201.225 ;
        RECT 1.600 200.600 2.400 200.775 ;
        RECT 7.700 200.700 8.300 200.775 ;
        RECT 9.700 200.700 10.300 200.775 ;
        RECT 22.700 200.700 23.300 200.775 ;
        RECT 24.700 200.700 25.300 200.775 ;
        RECT 37.700 200.700 38.300 200.775 ;
        RECT 39.700 200.700 40.300 200.775 ;
        RECT 54.700 200.700 55.300 200.775 ;
        RECT 69.700 200.700 70.300 200.775 ;
        RECT 84.700 200.700 85.300 200.775 ;
        RECT 86.200 200.700 86.800 200.775 ;
        RECT 128.700 200.700 129.300 200.775 ;
        RECT 129.700 200.700 130.300 200.775 ;
        RECT 136.200 200.700 136.800 200.775 ;
        RECT 137.200 200.700 137.800 200.775 ;
        RECT 151.200 200.700 151.800 200.775 ;
        RECT 152.200 200.700 152.800 200.775 ;
        RECT 30.020 153.100 30.820 153.900 ;
        RECT 48.520 153.100 49.320 153.900 ;
        RECT 104.020 153.100 104.820 153.900 ;
        RECT 122.520 153.100 123.320 153.900 ;
        RECT 11.520 151.600 12.320 152.400 ;
        RECT 67.020 151.600 67.820 152.400 ;
        RECT 85.520 151.600 86.320 152.400 ;
        RECT 141.020 151.600 141.820 152.400 ;
        RECT 4.720 143.500 20.880 150.200 ;
        RECT 23.220 143.500 39.380 150.200 ;
        RECT 41.720 143.500 57.880 150.200 ;
        RECT 60.220 143.500 76.380 150.200 ;
        RECT 78.720 143.500 94.880 150.200 ;
        RECT 97.220 143.500 113.380 150.200 ;
        RECT 115.720 143.500 131.880 150.200 ;
        RECT 134.220 143.500 150.380 150.200 ;
        RECT 1.500 142.500 151.500 143.500 ;
        RECT 4.720 135.800 20.880 142.500 ;
        RECT 23.220 135.800 39.380 142.500 ;
        RECT 41.720 135.800 57.880 142.500 ;
        RECT 60.220 135.800 76.380 142.500 ;
        RECT 78.720 135.800 94.880 142.500 ;
        RECT 97.220 135.800 113.380 142.500 ;
        RECT 115.720 135.800 131.880 142.500 ;
        RECT 134.220 135.800 150.380 142.500 ;
        RECT 11.520 133.100 12.320 133.900 ;
        RECT 67.020 133.100 67.820 133.900 ;
        RECT 85.520 133.100 86.320 133.900 ;
        RECT 141.020 133.100 141.820 133.900 ;
        RECT 30.020 131.600 30.820 132.400 ;
        RECT 48.520 131.600 49.320 132.400 ;
        RECT 104.020 131.600 104.820 132.400 ;
        RECT 122.520 131.600 123.320 132.400 ;
        RECT 4.720 123.500 20.880 130.200 ;
        RECT 23.220 123.500 39.380 130.200 ;
        RECT 41.720 123.500 57.880 130.200 ;
        RECT 60.220 123.500 76.380 130.200 ;
        RECT 78.720 123.500 94.880 130.200 ;
        RECT 97.220 123.500 113.380 130.200 ;
        RECT 115.720 123.500 131.880 130.200 ;
        RECT 134.220 123.500 150.380 130.200 ;
        RECT 1.500 122.500 151.500 123.500 ;
        RECT 4.720 115.800 20.880 122.500 ;
        RECT 23.220 115.800 39.380 122.500 ;
        RECT 41.720 115.800 57.880 122.500 ;
        RECT 60.220 115.800 76.380 122.500 ;
        RECT 78.720 115.800 94.880 122.500 ;
        RECT 97.220 115.800 113.380 122.500 ;
        RECT 115.720 115.800 131.880 122.500 ;
        RECT 134.220 115.800 150.380 122.500 ;
        RECT 11.520 113.100 12.320 113.900 ;
        RECT 67.020 113.100 67.820 113.900 ;
        RECT 85.520 113.100 86.320 113.900 ;
        RECT 141.020 113.100 141.820 113.900 ;
        RECT 30.020 111.600 30.820 112.400 ;
        RECT 48.520 111.600 49.320 112.400 ;
        RECT 104.020 111.600 104.820 112.400 ;
        RECT 122.520 111.600 123.320 112.400 ;
        RECT 4.720 103.500 20.880 110.200 ;
        RECT 23.220 103.500 39.380 110.200 ;
        RECT 41.720 103.500 57.880 110.200 ;
        RECT 60.220 103.500 76.380 110.200 ;
        RECT 78.720 103.500 94.880 110.200 ;
        RECT 97.220 103.500 113.380 110.200 ;
        RECT 115.720 103.500 131.880 110.200 ;
        RECT 134.220 103.500 150.380 110.200 ;
        RECT 1.500 102.500 151.500 103.500 ;
        RECT 4.720 95.800 20.880 102.500 ;
        RECT 23.220 95.800 39.380 102.500 ;
        RECT 41.720 95.800 57.880 102.500 ;
        RECT 60.220 95.800 76.380 102.500 ;
        RECT 78.720 95.800 94.880 102.500 ;
        RECT 97.220 95.800 113.380 102.500 ;
        RECT 115.720 95.800 131.880 102.500 ;
        RECT 134.220 95.800 150.380 102.500 ;
        RECT 30.020 93.100 30.820 93.900 ;
        RECT 48.520 93.100 49.320 93.900 ;
        RECT 104.020 93.100 104.820 93.900 ;
        RECT 122.520 93.100 123.320 93.900 ;
        RECT 11.520 91.600 12.320 92.400 ;
        RECT 67.020 91.600 67.820 92.400 ;
        RECT 85.520 91.600 86.320 92.400 ;
        RECT 141.020 91.600 141.820 92.400 ;
        RECT 4.720 83.500 20.880 90.200 ;
        RECT 23.220 83.500 39.380 90.200 ;
        RECT 41.720 83.500 57.880 90.200 ;
        RECT 60.220 83.500 76.380 90.200 ;
        RECT 78.720 83.500 94.880 90.200 ;
        RECT 97.220 83.500 113.380 90.200 ;
        RECT 115.720 83.500 131.880 90.200 ;
        RECT 134.220 83.500 150.380 90.200 ;
        RECT 1.500 82.500 151.500 83.500 ;
        RECT 4.720 75.800 20.880 82.500 ;
        RECT 23.220 75.800 39.380 82.500 ;
        RECT 41.720 75.800 57.880 82.500 ;
        RECT 60.220 75.800 76.380 82.500 ;
        RECT 78.720 75.800 94.880 82.500 ;
        RECT 97.220 75.800 113.380 82.500 ;
        RECT 115.720 75.800 131.880 82.500 ;
        RECT 134.220 75.800 150.380 82.500 ;
        RECT 68.200 74.225 68.800 74.300 ;
        RECT 86.200 74.225 86.800 74.300 ;
        RECT 92.200 74.225 92.800 74.300 ;
        RECT 110.700 74.225 111.300 74.300 ;
        RECT 112.200 74.225 112.800 74.300 ;
        RECT 3.775 73.775 155.225 74.225 ;
        RECT 68.200 73.700 68.800 73.775 ;
        RECT 86.200 73.700 86.800 73.775 ;
        RECT 92.200 73.700 92.800 73.775 ;
        RECT 110.700 73.700 111.300 73.775 ;
        RECT 112.200 73.700 112.800 73.775 ;
        RECT 41.200 73.025 41.800 73.100 ;
        RECT 45.520 73.025 46.120 73.100 ;
        RECT 3.775 72.575 155.225 73.025 ;
        RECT 41.200 72.500 41.800 72.575 ;
        RECT 45.520 72.500 46.120 72.575 ;
        RECT 30.820 71.825 31.420 71.900 ;
        RECT 66.700 71.825 67.300 71.900 ;
        RECT 78.700 71.825 79.300 71.900 ;
        RECT 3.775 71.375 155.225 71.825 ;
        RECT 30.820 71.300 31.420 71.375 ;
        RECT 66.700 71.300 67.300 71.375 ;
        RECT 78.700 71.300 79.300 71.375 ;
        RECT 64.700 70.625 65.300 70.700 ;
        RECT 71.200 70.625 71.800 70.700 ;
        RECT 3.775 70.175 155.225 70.625 ;
        RECT 64.700 70.100 65.300 70.175 ;
        RECT 71.200 70.100 71.800 70.175 ;
        RECT 63.700 69.425 64.300 69.500 ;
        RECT 90.700 69.425 91.300 69.500 ;
        RECT 108.700 69.425 109.300 69.500 ;
        RECT 3.775 68.975 155.225 69.425 ;
        RECT 63.700 68.900 64.300 68.975 ;
        RECT 90.700 68.900 91.300 68.975 ;
        RECT 108.700 68.900 109.300 68.975 ;
        RECT 56.200 68.225 56.800 68.300 ;
        RECT 88.700 68.225 89.300 68.300 ;
        RECT 3.775 67.775 155.225 68.225 ;
        RECT 56.200 67.700 56.800 67.775 ;
        RECT 88.700 67.700 89.300 67.775 ;
        RECT 30.720 55.600 31.520 56.400 ;
        RECT 17.920 24.800 46.080 51.200 ;
        RECT 45.420 20.600 46.220 21.400 ;
        RECT 48.700 8.225 49.300 8.300 ;
        RECT 113.320 8.225 113.920 8.300 ;
        RECT 48.700 7.775 113.920 8.225 ;
        RECT 48.700 7.700 49.300 7.775 ;
        RECT 113.320 7.700 113.920 7.775 ;
        RECT 41.200 6.225 41.800 6.300 ;
        RECT 132.640 6.225 133.240 6.300 ;
        RECT 41.200 5.775 133.240 6.225 ;
        RECT 41.200 5.700 41.800 5.775 ;
        RECT 132.640 5.700 133.240 5.775 ;
        RECT 33.700 4.225 34.300 4.300 ;
        RECT 151.960 4.225 152.560 4.300 ;
        RECT 33.700 3.775 152.560 4.225 ;
        RECT 33.700 3.700 34.300 3.775 ;
        RECT 151.960 3.700 152.560 3.775 ;
        RECT 1.600 2.025 2.400 2.200 ;
        RECT 1.600 1.575 100.225 2.025 ;
        RECT 1.600 1.400 2.400 1.575 ;
        RECT 113.220 0.350 114.020 1.150 ;
        RECT 132.540 0.350 133.340 1.150 ;
        RECT 151.860 0.350 152.660 1.150 ;
      LAYER met4 ;
        RECT 30.420 224.760 30.670 225.400 ;
        RECT 30.970 224.760 31.220 225.400 ;
        RECT 30.420 224.600 31.220 224.760 ;
        RECT 33.180 224.760 33.430 225.400 ;
        RECT 33.730 224.760 33.980 225.400 ;
        RECT 33.180 224.600 33.980 224.760 ;
        RECT 35.940 224.760 36.190 225.400 ;
        RECT 36.490 224.760 36.740 225.400 ;
        RECT 35.940 224.600 36.740 224.760 ;
        RECT 38.700 224.760 38.950 225.400 ;
        RECT 39.250 224.760 39.500 225.400 ;
        RECT 38.700 224.600 39.500 224.760 ;
        RECT 41.460 224.760 41.710 225.400 ;
        RECT 42.010 224.760 42.260 225.400 ;
        RECT 41.460 224.600 42.260 224.760 ;
        RECT 44.220 224.760 44.470 225.400 ;
        RECT 44.770 224.760 45.020 225.400 ;
        RECT 44.220 224.600 45.020 224.760 ;
        RECT 46.980 224.760 47.230 225.400 ;
        RECT 47.530 224.760 47.780 225.400 ;
        RECT 46.980 224.600 47.780 224.760 ;
        RECT 49.740 224.760 49.990 225.400 ;
        RECT 50.290 224.760 50.540 225.400 ;
        RECT 49.740 224.600 50.540 224.760 ;
        RECT 52.500 224.760 52.750 225.400 ;
        RECT 53.050 224.760 53.300 225.400 ;
        RECT 52.500 224.600 53.300 224.760 ;
        RECT 55.260 224.760 55.510 225.400 ;
        RECT 55.810 224.760 56.060 225.400 ;
        RECT 55.260 224.600 56.060 224.760 ;
        RECT 58.020 224.760 58.270 225.400 ;
        RECT 58.570 224.760 58.820 225.400 ;
        RECT 58.020 224.600 58.820 224.760 ;
        RECT 60.780 224.760 61.030 225.400 ;
        RECT 61.330 224.760 61.580 225.400 ;
        RECT 60.780 224.600 61.580 224.760 ;
        RECT 63.540 224.760 63.790 225.400 ;
        RECT 64.090 224.760 64.340 225.400 ;
        RECT 63.540 224.600 64.340 224.760 ;
        RECT 66.300 224.760 66.550 225.400 ;
        RECT 66.850 224.760 67.100 225.400 ;
        RECT 66.300 224.600 67.100 224.760 ;
        RECT 69.060 224.760 69.310 225.400 ;
        RECT 69.610 224.760 69.860 225.400 ;
        RECT 69.060 224.600 69.860 224.760 ;
        RECT 71.820 224.760 72.070 225.400 ;
        RECT 72.370 224.760 72.620 225.400 ;
        RECT 71.820 224.600 72.620 224.760 ;
        RECT 74.580 224.760 74.830 225.400 ;
        RECT 75.130 224.760 75.380 225.400 ;
        RECT 74.580 224.600 75.380 224.760 ;
        RECT 77.340 224.760 77.590 225.400 ;
        RECT 77.890 224.760 78.140 225.400 ;
        RECT 77.340 224.600 78.140 224.760 ;
        RECT 80.100 224.760 80.350 225.400 ;
        RECT 80.650 224.760 80.900 225.400 ;
        RECT 80.100 224.600 80.900 224.760 ;
        RECT 82.860 224.760 83.110 225.400 ;
        RECT 83.410 224.760 83.660 225.400 ;
        RECT 82.860 224.600 83.660 224.760 ;
        RECT 85.620 224.760 85.870 225.400 ;
        RECT 86.170 224.760 86.420 225.400 ;
        RECT 85.620 224.600 86.420 224.760 ;
        RECT 88.380 224.760 88.630 225.400 ;
        RECT 88.930 224.760 89.180 225.400 ;
        RECT 88.380 224.600 89.180 224.760 ;
        RECT 91.140 224.760 91.390 225.400 ;
        RECT 91.690 224.760 91.940 225.400 ;
        RECT 91.140 224.600 91.940 224.760 ;
        RECT 93.900 224.760 94.150 225.400 ;
        RECT 94.450 224.760 94.700 225.400 ;
        RECT 93.900 224.600 94.700 224.760 ;
        RECT 132.540 224.760 132.790 225.400 ;
        RECT 133.090 224.760 133.340 225.400 ;
        RECT 132.540 224.600 133.340 224.760 ;
        RECT 135.300 224.760 135.550 225.400 ;
        RECT 135.850 224.760 136.100 225.400 ;
        RECT 135.300 224.600 136.100 224.760 ;
        RECT 138.060 224.760 138.310 225.400 ;
        RECT 138.610 224.760 138.860 225.400 ;
        RECT 138.060 224.600 138.860 224.760 ;
        RECT 30.020 153.100 30.820 153.900 ;
        RECT 48.520 153.100 49.320 153.900 ;
        RECT 104.020 153.100 104.820 153.900 ;
        RECT 122.520 153.100 123.320 153.900 ;
        RECT 11.520 151.600 12.320 152.400 ;
        RECT 11.570 149.805 12.270 151.600 ;
        RECT 5.115 136.195 18.725 149.805 ;
        RECT 20.380 135.860 20.860 150.140 ;
        RECT 21.750 143.400 22.350 152.300 ;
        RECT 30.070 149.805 30.770 153.100 ;
        RECT 21.650 142.600 22.450 143.400 ;
        RECT 11.520 133.100 12.320 133.900 ;
        RECT 11.570 129.805 12.270 133.100 ;
        RECT 5.115 116.195 18.725 129.805 ;
        RECT 20.380 115.860 20.860 130.140 ;
        RECT 21.750 123.400 22.350 142.600 ;
        RECT 23.615 136.195 37.225 149.805 ;
        RECT 38.880 135.860 39.360 150.140 ;
        RECT 40.250 143.400 40.850 152.300 ;
        RECT 48.570 149.805 49.270 153.100 ;
        RECT 40.150 142.600 40.950 143.400 ;
        RECT 30.020 131.600 30.820 132.400 ;
        RECT 30.070 129.805 30.770 131.600 ;
        RECT 21.650 122.600 22.450 123.400 ;
        RECT 11.520 113.100 12.320 113.900 ;
        RECT 11.570 109.805 12.270 113.100 ;
        RECT 5.115 96.195 18.725 109.805 ;
        RECT 20.380 95.860 20.860 110.140 ;
        RECT 21.750 103.400 22.350 122.600 ;
        RECT 23.615 116.195 37.225 129.805 ;
        RECT 38.880 115.860 39.360 130.140 ;
        RECT 40.250 123.400 40.850 142.600 ;
        RECT 42.115 136.195 55.725 149.805 ;
        RECT 57.380 135.860 57.860 150.140 ;
        RECT 58.750 143.400 59.350 152.300 ;
        RECT 67.020 151.600 67.820 152.400 ;
        RECT 67.070 149.805 67.770 151.600 ;
        RECT 58.650 142.600 59.450 143.400 ;
        RECT 48.520 131.600 49.320 132.400 ;
        RECT 48.570 129.805 49.270 131.600 ;
        RECT 40.150 122.600 40.950 123.400 ;
        RECT 30.020 111.600 30.820 112.400 ;
        RECT 30.070 109.805 30.770 111.600 ;
        RECT 21.650 102.600 22.450 103.400 ;
        RECT 11.520 91.600 12.320 92.400 ;
        RECT 11.570 89.805 12.270 91.600 ;
        RECT 5.115 76.195 18.725 89.805 ;
        RECT 20.380 75.860 20.860 90.140 ;
        RECT 21.750 83.400 22.350 102.600 ;
        RECT 23.615 96.195 37.225 109.805 ;
        RECT 38.880 95.860 39.360 110.140 ;
        RECT 40.250 103.400 40.850 122.600 ;
        RECT 42.115 116.195 55.725 129.805 ;
        RECT 57.380 115.860 57.860 130.140 ;
        RECT 58.750 123.400 59.350 142.600 ;
        RECT 60.615 136.195 74.225 149.805 ;
        RECT 75.880 135.860 76.360 150.140 ;
        RECT 77.250 143.400 77.850 152.300 ;
        RECT 85.520 151.600 86.320 152.400 ;
        RECT 85.570 149.805 86.270 151.600 ;
        RECT 77.150 142.600 77.950 143.400 ;
        RECT 67.020 133.100 67.820 133.900 ;
        RECT 67.070 129.805 67.770 133.100 ;
        RECT 58.650 122.600 59.450 123.400 ;
        RECT 48.520 111.600 49.320 112.400 ;
        RECT 48.570 109.805 49.270 111.600 ;
        RECT 40.150 102.600 40.950 103.400 ;
        RECT 30.020 93.100 30.820 93.900 ;
        RECT 30.070 89.805 30.770 93.100 ;
        RECT 21.650 82.600 22.450 83.400 ;
        RECT 21.750 79.700 22.350 82.600 ;
        RECT 23.615 76.195 37.225 89.805 ;
        RECT 38.880 75.860 39.360 90.140 ;
        RECT 40.250 83.400 40.850 102.600 ;
        RECT 42.115 96.195 55.725 109.805 ;
        RECT 57.380 95.860 57.860 110.140 ;
        RECT 58.750 103.400 59.350 122.600 ;
        RECT 60.615 116.195 74.225 129.805 ;
        RECT 75.880 115.860 76.360 130.140 ;
        RECT 77.250 123.400 77.850 142.600 ;
        RECT 79.115 136.195 92.725 149.805 ;
        RECT 94.380 135.860 94.860 150.140 ;
        RECT 95.750 143.400 96.350 152.300 ;
        RECT 104.070 149.805 104.770 153.100 ;
        RECT 95.650 142.600 96.450 143.400 ;
        RECT 85.520 133.100 86.320 133.900 ;
        RECT 85.570 129.805 86.270 133.100 ;
        RECT 77.150 122.600 77.950 123.400 ;
        RECT 67.020 113.100 67.820 113.900 ;
        RECT 67.070 109.805 67.770 113.100 ;
        RECT 58.650 102.600 59.450 103.400 ;
        RECT 48.520 93.100 49.320 93.900 ;
        RECT 48.570 89.805 49.270 93.100 ;
        RECT 40.150 82.600 40.950 83.400 ;
        RECT 40.250 79.700 40.850 82.600 ;
        RECT 42.115 76.195 55.725 89.805 ;
        RECT 57.380 75.860 57.860 90.140 ;
        RECT 58.750 83.400 59.350 102.600 ;
        RECT 60.615 96.195 74.225 109.805 ;
        RECT 75.880 95.860 76.360 110.140 ;
        RECT 77.250 103.400 77.850 122.600 ;
        RECT 79.115 116.195 92.725 129.805 ;
        RECT 94.380 115.860 94.860 130.140 ;
        RECT 95.750 123.400 96.350 142.600 ;
        RECT 97.615 136.195 111.225 149.805 ;
        RECT 112.880 135.860 113.360 150.140 ;
        RECT 114.250 143.400 114.850 152.300 ;
        RECT 122.570 149.805 123.270 153.100 ;
        RECT 114.150 142.600 114.950 143.400 ;
        RECT 104.020 131.600 104.820 132.400 ;
        RECT 104.070 129.805 104.770 131.600 ;
        RECT 95.650 122.600 96.450 123.400 ;
        RECT 85.520 113.100 86.320 113.900 ;
        RECT 85.570 109.805 86.270 113.100 ;
        RECT 77.150 102.600 77.950 103.400 ;
        RECT 67.020 91.600 67.820 92.400 ;
        RECT 67.070 89.805 67.770 91.600 ;
        RECT 58.650 82.600 59.450 83.400 ;
        RECT 58.750 79.700 59.350 82.600 ;
        RECT 60.615 76.195 74.225 89.805 ;
        RECT 75.880 75.860 76.360 90.140 ;
        RECT 77.250 83.400 77.850 102.600 ;
        RECT 79.115 96.195 92.725 109.805 ;
        RECT 94.380 95.860 94.860 110.140 ;
        RECT 95.750 103.400 96.350 122.600 ;
        RECT 97.615 116.195 111.225 129.805 ;
        RECT 112.880 115.860 113.360 130.140 ;
        RECT 114.250 123.400 114.850 142.600 ;
        RECT 116.115 136.195 129.725 149.805 ;
        RECT 131.380 135.860 131.860 150.140 ;
        RECT 132.750 143.400 133.350 152.300 ;
        RECT 141.020 151.600 141.820 152.400 ;
        RECT 141.070 149.805 141.770 151.600 ;
        RECT 132.650 142.600 133.450 143.400 ;
        RECT 122.520 131.600 123.320 132.400 ;
        RECT 122.570 129.805 123.270 131.600 ;
        RECT 114.150 122.600 114.950 123.400 ;
        RECT 104.020 111.600 104.820 112.400 ;
        RECT 104.070 109.805 104.770 111.600 ;
        RECT 95.650 102.600 96.450 103.400 ;
        RECT 85.520 91.600 86.320 92.400 ;
        RECT 85.570 89.805 86.270 91.600 ;
        RECT 77.150 82.600 77.950 83.400 ;
        RECT 77.250 79.700 77.850 82.600 ;
        RECT 79.115 76.195 92.725 89.805 ;
        RECT 94.380 75.860 94.860 90.140 ;
        RECT 95.750 83.400 96.350 102.600 ;
        RECT 97.615 96.195 111.225 109.805 ;
        RECT 112.880 95.860 113.360 110.140 ;
        RECT 114.250 103.400 114.850 122.600 ;
        RECT 116.115 116.195 129.725 129.805 ;
        RECT 131.380 115.860 131.860 130.140 ;
        RECT 132.750 123.400 133.350 142.600 ;
        RECT 134.615 136.195 148.225 149.805 ;
        RECT 149.880 135.860 150.360 150.140 ;
        RECT 141.020 133.100 141.820 133.900 ;
        RECT 141.070 129.805 141.770 133.100 ;
        RECT 132.650 122.600 133.450 123.400 ;
        RECT 122.520 111.600 123.320 112.400 ;
        RECT 122.570 109.805 123.270 111.600 ;
        RECT 114.150 102.600 114.950 103.400 ;
        RECT 104.020 93.100 104.820 93.900 ;
        RECT 104.070 89.805 104.770 93.100 ;
        RECT 95.650 82.600 96.450 83.400 ;
        RECT 95.750 79.700 96.350 82.600 ;
        RECT 97.615 76.195 111.225 89.805 ;
        RECT 112.880 75.860 113.360 90.140 ;
        RECT 114.250 83.400 114.850 102.600 ;
        RECT 116.115 96.195 129.725 109.805 ;
        RECT 131.380 95.860 131.860 110.140 ;
        RECT 132.750 103.400 133.350 122.600 ;
        RECT 134.615 116.195 148.225 129.805 ;
        RECT 149.880 115.860 150.360 130.140 ;
        RECT 141.020 113.100 141.820 113.900 ;
        RECT 141.070 109.805 141.770 113.100 ;
        RECT 132.650 102.600 133.450 103.400 ;
        RECT 122.520 93.100 123.320 93.900 ;
        RECT 122.570 89.805 123.270 93.100 ;
        RECT 114.150 82.600 114.950 83.400 ;
        RECT 114.250 79.700 114.850 82.600 ;
        RECT 116.115 76.195 129.725 89.805 ;
        RECT 131.380 75.860 131.860 90.140 ;
        RECT 132.750 83.400 133.350 102.600 ;
        RECT 134.615 96.195 148.225 109.805 ;
        RECT 149.880 95.860 150.360 110.140 ;
        RECT 141.020 91.600 141.820 92.400 ;
        RECT 141.070 89.805 141.770 91.600 ;
        RECT 132.650 82.600 133.450 83.400 ;
        RECT 132.750 79.700 133.350 82.600 ;
        RECT 134.615 76.195 148.225 89.805 ;
        RECT 149.880 75.860 150.360 90.140 ;
        RECT 30.720 55.600 31.520 56.400 ;
        RECT 30.770 50.805 31.470 55.600 ;
        RECT 18.315 25.195 43.925 50.805 ;
        RECT 45.580 38.350 46.060 51.140 ;
        RECT 45.470 21.400 46.170 38.350 ;
        RECT 45.420 20.600 46.220 21.400 ;
        RECT 113.220 1.000 114.020 1.150 ;
        RECT 132.540 1.000 133.340 1.150 ;
        RECT 151.860 1.000 152.660 1.150 ;
  END
END tt_um_jonah_suarez_dac
END LIBRARY

